VERSION 5.7 ;
BUSBITCHARS "[]" ;
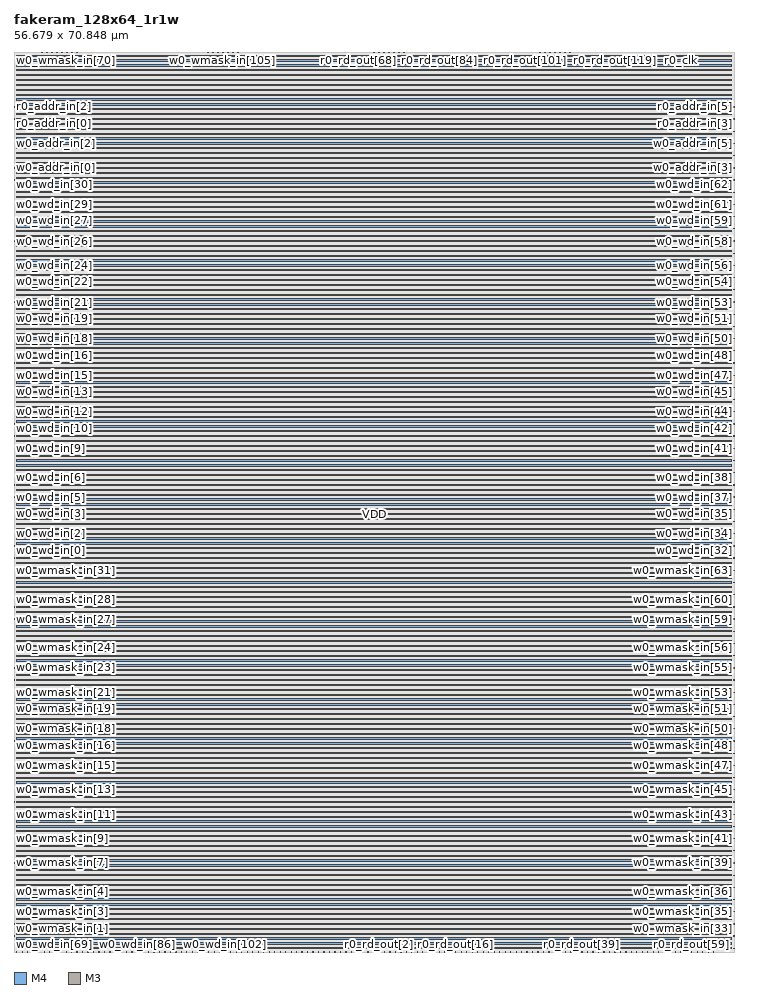
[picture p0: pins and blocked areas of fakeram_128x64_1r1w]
MACRO fakeram_128x64_1r1w
  FOREIGN fakeram_128x64_1r1w 0 0 ;
  SYMMETRY X Y R90 ;
  SIZE 56.679 BY 70.848 ;
  CLASS BLOCK ;
  PIN w0_wmask_in[0]
    DIRECTION INPUT ;
    USE SIGNAL ;
    SHAPE ABUTMENT ;
    PORT
      LAYER M4 ;
      RECT 0.000 0.276 0.072 0.300 ;
    END
  END w0_wmask_in[0]
  PIN w0_wmask_in[1]
    DIRECTION INPUT ;
    USE SIGNAL ;
    SHAPE ABUTMENT ;
    PORT
      LAYER M4 ;
      RECT 0.000 1.236 0.072 1.260 ;
    END
  END w0_wmask_in[1]
  PIN w0_wmask_in[2]
    DIRECTION INPUT ;
    USE SIGNAL ;
    SHAPE ABUTMENT ;
    PORT
      LAYER M4 ;
      RECT 0.000 2.196 0.072 2.220 ;
    END
  END w0_wmask_in[2]
  PIN w0_wmask_in[3]
    DIRECTION INPUT ;
    USE SIGNAL ;
    SHAPE ABUTMENT ;
    PORT
      LAYER M4 ;
      RECT 0.000 3.156 0.072 3.180 ;
    END
  END w0_wmask_in[3]
  PIN w0_wmask_in[4]
    DIRECTION INPUT ;
    USE SIGNAL ;
    SHAPE ABUTMENT ;
    PORT
      LAYER M4 ;
      RECT 0.000 4.116 0.072 4.140 ;
    END
  END w0_wmask_in[4]
  PIN w0_wmask_in[5]
    DIRECTION INPUT ;
    USE SIGNAL ;
    SHAPE ABUTMENT ;
    PORT
      LAYER M4 ;
      RECT 0.000 5.076 0.072 5.100 ;
    END
  END w0_wmask_in[5]
  PIN w0_wmask_in[6]
    DIRECTION INPUT ;
    USE SIGNAL ;
    SHAPE ABUTMENT ;
    PORT
      LAYER M4 ;
      RECT 0.000 6.036 0.072 6.060 ;
    END
  END w0_wmask_in[6]
  PIN w0_wmask_in[7]
    DIRECTION INPUT ;
    USE SIGNAL ;
    SHAPE ABUTMENT ;
    PORT
      LAYER M4 ;
      RECT 0.000 6.996 0.072 7.020 ;
    END
  END w0_wmask_in[7]
  PIN w0_wmask_in[8]
    DIRECTION INPUT ;
    USE SIGNAL ;
    SHAPE ABUTMENT ;
    PORT
      LAYER M4 ;
      RECT 0.000 7.956 0.072 7.980 ;
    END
  END w0_wmask_in[8]
  PIN w0_wmask_in[9]
    DIRECTION INPUT ;
    USE SIGNAL ;
    SHAPE ABUTMENT ;
    PORT
      LAYER M4 ;
      RECT 0.000 8.916 0.072 8.940 ;
    END
  END w0_wmask_in[9]
  PIN w0_wmask_in[10]
    DIRECTION INPUT ;
    USE SIGNAL ;
    SHAPE ABUTMENT ;
    PORT
      LAYER M4 ;
      RECT 0.000 9.876 0.072 9.900 ;
    END
  END w0_wmask_in[10]
  PIN w0_wmask_in[11]
    DIRECTION INPUT ;
    USE SIGNAL ;
    SHAPE ABUTMENT ;
    PORT
      LAYER M4 ;
      RECT 0.000 10.836 0.072 10.860 ;
    END
  END w0_wmask_in[11]
  PIN w0_wmask_in[12]
    DIRECTION INPUT ;
    USE SIGNAL ;
    SHAPE ABUTMENT ;
    PORT
      LAYER M4 ;
      RECT 0.000 11.796 0.072 11.820 ;
    END
  END w0_wmask_in[12]
  PIN w0_wmask_in[13]
    DIRECTION INPUT ;
    USE SIGNAL ;
    SHAPE ABUTMENT ;
    PORT
      LAYER M4 ;
      RECT 0.000 12.756 0.072 12.780 ;
    END
  END w0_wmask_in[13]
  PIN w0_wmask_in[14]
    DIRECTION INPUT ;
    USE SIGNAL ;
    SHAPE ABUTMENT ;
    PORT
      LAYER M4 ;
      RECT 0.000 13.716 0.072 13.740 ;
    END
  END w0_wmask_in[14]
  PIN w0_wmask_in[15]
    DIRECTION INPUT ;
    USE SIGNAL ;
    SHAPE ABUTMENT ;
    PORT
      LAYER M4 ;
      RECT 0.000 14.676 0.072 14.700 ;
    END
  END w0_wmask_in[15]
  PIN w0_wmask_in[16]
    DIRECTION INPUT ;
    USE SIGNAL ;
    SHAPE ABUTMENT ;
    PORT
      LAYER M4 ;
      RECT 0.000 15.636 0.072 15.660 ;
    END
  END w0_wmask_in[16]
  PIN w0_wmask_in[17]
    DIRECTION INPUT ;
    USE SIGNAL ;
    SHAPE ABUTMENT ;
    PORT
      LAYER M4 ;
      RECT 0.000 16.596 0.072 16.620 ;
    END
  END w0_wmask_in[17]
  PIN w0_wmask_in[18]
    DIRECTION INPUT ;
    USE SIGNAL ;
    SHAPE ABUTMENT ;
    PORT
      LAYER M4 ;
      RECT 0.000 17.556 0.072 17.580 ;
    END
  END w0_wmask_in[18]
  PIN w0_wmask_in[19]
    DIRECTION INPUT ;
    USE SIGNAL ;
    SHAPE ABUTMENT ;
    PORT
      LAYER M4 ;
      RECT 0.000 18.516 0.072 18.540 ;
    END
  END w0_wmask_in[19]
  PIN w0_wmask_in[20]
    DIRECTION INPUT ;
    USE SIGNAL ;
    SHAPE ABUTMENT ;
    PORT
      LAYER M4 ;
      RECT 0.000 19.476 0.072 19.500 ;
    END
  END w0_wmask_in[20]
  PIN w0_wmask_in[21]
    DIRECTION INPUT ;
    USE SIGNAL ;
    SHAPE ABUTMENT ;
    PORT
      LAYER M4 ;
      RECT 0.000 20.436 0.072 20.460 ;
    END
  END w0_wmask_in[21]
  PIN w0_wmask_in[22]
    DIRECTION INPUT ;
    USE SIGNAL ;
    SHAPE ABUTMENT ;
    PORT
      LAYER M4 ;
      RECT 0.000 21.396 0.072 21.420 ;
    END
  END w0_wmask_in[22]
  PIN w0_wmask_in[23]
    DIRECTION INPUT ;
    USE SIGNAL ;
    SHAPE ABUTMENT ;
    PORT
      LAYER M4 ;
      RECT 0.000 22.356 0.072 22.380 ;
    END
  END w0_wmask_in[23]
  PIN w0_wmask_in[24]
    DIRECTION INPUT ;
    USE SIGNAL ;
    SHAPE ABUTMENT ;
    PORT
      LAYER M4 ;
      RECT 0.000 23.316 0.072 23.340 ;
    END
  END w0_wmask_in[24]
  PIN w0_wmask_in[25]
    DIRECTION INPUT ;
    USE SIGNAL ;
    SHAPE ABUTMENT ;
    PORT
      LAYER M4 ;
      RECT 0.000 24.276 0.072 24.300 ;
    END
  END w0_wmask_in[25]
  PIN w0_wmask_in[26]
    DIRECTION INPUT ;
    USE SIGNAL ;
    SHAPE ABUTMENT ;
    PORT
      LAYER M4 ;
      RECT 0.000 25.236 0.072 25.260 ;
    END
  END w0_wmask_in[26]
  PIN w0_wmask_in[27]
    DIRECTION INPUT ;
    USE SIGNAL ;
    SHAPE ABUTMENT ;
    PORT
      LAYER M4 ;
      RECT 0.000 26.196 0.072 26.220 ;
    END
  END w0_wmask_in[27]
  PIN w0_wmask_in[28]
    DIRECTION INPUT ;
    USE SIGNAL ;
    SHAPE ABUTMENT ;
    PORT
      LAYER M4 ;
      RECT 0.000 27.156 0.072 27.180 ;
    END
  END w0_wmask_in[28]
  PIN w0_wmask_in[29]
    DIRECTION INPUT ;
    USE SIGNAL ;
    SHAPE ABUTMENT ;
    PORT
      LAYER M4 ;
      RECT 0.000 28.116 0.072 28.140 ;
    END
  END w0_wmask_in[29]
  PIN w0_wmask_in[30]
    DIRECTION INPUT ;
    USE SIGNAL ;
    SHAPE ABUTMENT ;
    PORT
      LAYER M4 ;
      RECT 0.000 29.076 0.072 29.100 ;
    END
  END w0_wmask_in[30]
  PIN w0_wmask_in[31]
    DIRECTION INPUT ;
    USE SIGNAL ;
    SHAPE ABUTMENT ;
    PORT
      LAYER M4 ;
      RECT 0.000 30.036 0.072 30.060 ;
    END
  END w0_wmask_in[31]
  PIN w0_wmask_in[32]
    DIRECTION INPUT ;
    USE SIGNAL ;
    SHAPE ABUTMENT ;
    PORT
      LAYER M4 ;
      RECT 56.607 0.276 56.679 0.300 ;
    END
  END w0_wmask_in[32]
  PIN w0_wmask_in[33]
    DIRECTION INPUT ;
    USE SIGNAL ;
    SHAPE ABUTMENT ;
    PORT
      LAYER M4 ;
      RECT 56.607 1.236 56.679 1.260 ;
    END
  END w0_wmask_in[33]
  PIN w0_wmask_in[34]
    DIRECTION INPUT ;
    USE SIGNAL ;
    SHAPE ABUTMENT ;
    PORT
      LAYER M4 ;
      RECT 56.607 2.196 56.679 2.220 ;
    END
  END w0_wmask_in[34]
  PIN w0_wmask_in[35]
    DIRECTION INPUT ;
    USE SIGNAL ;
    SHAPE ABUTMENT ;
    PORT
      LAYER M4 ;
      RECT 56.607 3.156 56.679 3.180 ;
    END
  END w0_wmask_in[35]
  PIN w0_wmask_in[36]
    DIRECTION INPUT ;
    USE SIGNAL ;
    SHAPE ABUTMENT ;
    PORT
      LAYER M4 ;
      RECT 56.607 4.116 56.679 4.140 ;
    END
  END w0_wmask_in[36]
  PIN w0_wmask_in[37]
    DIRECTION INPUT ;
    USE SIGNAL ;
    SHAPE ABUTMENT ;
    PORT
      LAYER M4 ;
      RECT 56.607 5.076 56.679 5.100 ;
    END
  END w0_wmask_in[37]
  PIN w0_wmask_in[38]
    DIRECTION INPUT ;
    USE SIGNAL ;
    SHAPE ABUTMENT ;
    PORT
      LAYER M4 ;
      RECT 56.607 6.036 56.679 6.060 ;
    END
  END w0_wmask_in[38]
  PIN w0_wmask_in[39]
    DIRECTION INPUT ;
    USE SIGNAL ;
    SHAPE ABUTMENT ;
    PORT
      LAYER M4 ;
      RECT 56.607 6.996 56.679 7.020 ;
    END
  END w0_wmask_in[39]
  PIN w0_wmask_in[40]
    DIRECTION INPUT ;
    USE SIGNAL ;
    SHAPE ABUTMENT ;
    PORT
      LAYER M4 ;
      RECT 56.607 7.956 56.679 7.980 ;
    END
  END w0_wmask_in[40]
  PIN w0_wmask_in[41]
    DIRECTION INPUT ;
    USE SIGNAL ;
    SHAPE ABUTMENT ;
    PORT
      LAYER M4 ;
      RECT 56.607 8.916 56.679 8.940 ;
    END
  END w0_wmask_in[41]
  PIN w0_wmask_in[42]
    DIRECTION INPUT ;
    USE SIGNAL ;
    SHAPE ABUTMENT ;
    PORT
      LAYER M4 ;
      RECT 56.607 9.876 56.679 9.900 ;
    END
  END w0_wmask_in[42]
  PIN w0_wmask_in[43]
    DIRECTION INPUT ;
    USE SIGNAL ;
    SHAPE ABUTMENT ;
    PORT
      LAYER M4 ;
      RECT 56.607 10.836 56.679 10.860 ;
    END
  END w0_wmask_in[43]
  PIN w0_wmask_in[44]
    DIRECTION INPUT ;
    USE SIGNAL ;
    SHAPE ABUTMENT ;
    PORT
      LAYER M4 ;
      RECT 56.607 11.796 56.679 11.820 ;
    END
  END w0_wmask_in[44]
  PIN w0_wmask_in[45]
    DIRECTION INPUT ;
    USE SIGNAL ;
    SHAPE ABUTMENT ;
    PORT
      LAYER M4 ;
      RECT 56.607 12.756 56.679 12.780 ;
    END
  END w0_wmask_in[45]
  PIN w0_wmask_in[46]
    DIRECTION INPUT ;
    USE SIGNAL ;
    SHAPE ABUTMENT ;
    PORT
      LAYER M4 ;
      RECT 56.607 13.716 56.679 13.740 ;
    END
  END w0_wmask_in[46]
  PIN w0_wmask_in[47]
    DIRECTION INPUT ;
    USE SIGNAL ;
    SHAPE ABUTMENT ;
    PORT
      LAYER M4 ;
      RECT 56.607 14.676 56.679 14.700 ;
    END
  END w0_wmask_in[47]
  PIN w0_wmask_in[48]
    DIRECTION INPUT ;
    USE SIGNAL ;
    SHAPE ABUTMENT ;
    PORT
      LAYER M4 ;
      RECT 56.607 15.636 56.679 15.660 ;
    END
  END w0_wmask_in[48]
  PIN w0_wmask_in[49]
    DIRECTION INPUT ;
    USE SIGNAL ;
    SHAPE ABUTMENT ;
    PORT
      LAYER M4 ;
      RECT 56.607 16.596 56.679 16.620 ;
    END
  END w0_wmask_in[49]
  PIN w0_wmask_in[50]
    DIRECTION INPUT ;
    USE SIGNAL ;
    SHAPE ABUTMENT ;
    PORT
      LAYER M4 ;
      RECT 56.607 17.556 56.679 17.580 ;
    END
  END w0_wmask_in[50]
  PIN w0_wmask_in[51]
    DIRECTION INPUT ;
    USE SIGNAL ;
    SHAPE ABUTMENT ;
    PORT
      LAYER M4 ;
      RECT 56.607 18.516 56.679 18.540 ;
    END
  END w0_wmask_in[51]
  PIN w0_wmask_in[52]
    DIRECTION INPUT ;
    USE SIGNAL ;
    SHAPE ABUTMENT ;
    PORT
      LAYER M4 ;
      RECT 56.607 19.476 56.679 19.500 ;
    END
  END w0_wmask_in[52]
  PIN w0_wmask_in[53]
    DIRECTION INPUT ;
    USE SIGNAL ;
    SHAPE ABUTMENT ;
    PORT
      LAYER M4 ;
      RECT 56.607 20.436 56.679 20.460 ;
    END
  END w0_wmask_in[53]
  PIN w0_wmask_in[54]
    DIRECTION INPUT ;
    USE SIGNAL ;
    SHAPE ABUTMENT ;
    PORT
      LAYER M4 ;
      RECT 56.607 21.396 56.679 21.420 ;
    END
  END w0_wmask_in[54]
  PIN w0_wmask_in[55]
    DIRECTION INPUT ;
    USE SIGNAL ;
    SHAPE ABUTMENT ;
    PORT
      LAYER M4 ;
      RECT 56.607 22.356 56.679 22.380 ;
    END
  END w0_wmask_in[55]
  PIN w0_wmask_in[56]
    DIRECTION INPUT ;
    USE SIGNAL ;
    SHAPE ABUTMENT ;
    PORT
      LAYER M4 ;
      RECT 56.607 23.316 56.679 23.340 ;
    END
  END w0_wmask_in[56]
  PIN w0_wmask_in[57]
    DIRECTION INPUT ;
    USE SIGNAL ;
    SHAPE ABUTMENT ;
    PORT
      LAYER M4 ;
      RECT 56.607 24.276 56.679 24.300 ;
    END
  END w0_wmask_in[57]
  PIN w0_wmask_in[58]
    DIRECTION INPUT ;
    USE SIGNAL ;
    SHAPE ABUTMENT ;
    PORT
      LAYER M4 ;
      RECT 56.607 25.236 56.679 25.260 ;
    END
  END w0_wmask_in[58]
  PIN w0_wmask_in[59]
    DIRECTION INPUT ;
    USE SIGNAL ;
    SHAPE ABUTMENT ;
    PORT
      LAYER M4 ;
      RECT 56.607 26.196 56.679 26.220 ;
    END
  END w0_wmask_in[59]
  PIN w0_wmask_in[60]
    DIRECTION INPUT ;
    USE SIGNAL ;
    SHAPE ABUTMENT ;
    PORT
      LAYER M4 ;
      RECT 56.607 27.156 56.679 27.180 ;
    END
  END w0_wmask_in[60]
  PIN w0_wmask_in[61]
    DIRECTION INPUT ;
    USE SIGNAL ;
    SHAPE ABUTMENT ;
    PORT
      LAYER M4 ;
      RECT 56.607 28.116 56.679 28.140 ;
    END
  END w0_wmask_in[61]
  PIN w0_wmask_in[62]
    DIRECTION INPUT ;
    USE SIGNAL ;
    SHAPE ABUTMENT ;
    PORT
      LAYER M4 ;
      RECT 56.607 29.076 56.679 29.100 ;
    END
  END w0_wmask_in[62]
  PIN w0_wmask_in[63]
    DIRECTION INPUT ;
    USE SIGNAL ;
    SHAPE ABUTMENT ;
    PORT
      LAYER M4 ;
      RECT 56.607 30.036 56.679 30.060 ;
    END
  END w0_wmask_in[63]
  PIN w0_wmask_in[64]
    DIRECTION INPUT ;
    USE SIGNAL ;
    SHAPE ABUTMENT ;
    PORT
      LAYER M3 ;
      RECT 0.207 70.794 0.225 70.848 ;
    END
  END w0_wmask_in[64]
  PIN w0_wmask_in[65]
    DIRECTION INPUT ;
    USE SIGNAL ;
    SHAPE ABUTMENT ;
    PORT
      LAYER M3 ;
      RECT 0.603 70.794 0.621 70.848 ;
    END
  END w0_wmask_in[65]
  PIN w0_wmask_in[66]
    DIRECTION INPUT ;
    USE SIGNAL ;
    SHAPE ABUTMENT ;
    PORT
      LAYER M3 ;
      RECT 0.999 70.794 1.017 70.848 ;
    END
  END w0_wmask_in[66]
  PIN w0_wmask_in[67]
    DIRECTION INPUT ;
    USE SIGNAL ;
    SHAPE ABUTMENT ;
    PORT
      LAYER M3 ;
      RECT 1.395 70.794 1.413 70.848 ;
    END
  END w0_wmask_in[67]
  PIN w0_wmask_in[68]
    DIRECTION INPUT ;
    USE SIGNAL ;
    SHAPE ABUTMENT ;
    PORT
      LAYER M3 ;
      RECT 1.791 70.794 1.809 70.848 ;
    END
  END w0_wmask_in[68]
  PIN w0_wmask_in[69]
    DIRECTION INPUT ;
    USE SIGNAL ;
    SHAPE ABUTMENT ;
    PORT
      LAYER M3 ;
      RECT 2.187 70.794 2.205 70.848 ;
    END
  END w0_wmask_in[69]
  PIN w0_wmask_in[70]
    DIRECTION INPUT ;
    USE SIGNAL ;
    SHAPE ABUTMENT ;
    PORT
      LAYER M3 ;
      RECT 2.583 70.794 2.601 70.848 ;
    END
  END w0_wmask_in[70]
  PIN w0_wmask_in[71]
    DIRECTION INPUT ;
    USE SIGNAL ;
    SHAPE ABUTMENT ;
    PORT
      LAYER M3 ;
      RECT 2.979 70.794 2.997 70.848 ;
    END
  END w0_wmask_in[71]
  PIN w0_wmask_in[72]
    DIRECTION INPUT ;
    USE SIGNAL ;
    SHAPE ABUTMENT ;
    PORT
      LAYER M3 ;
      RECT 3.375 70.794 3.393 70.848 ;
    END
  END w0_wmask_in[72]
  PIN w0_wmask_in[73]
    DIRECTION INPUT ;
    USE SIGNAL ;
    SHAPE ABUTMENT ;
    PORT
      LAYER M3 ;
      RECT 3.771 70.794 3.789 70.848 ;
    END
  END w0_wmask_in[73]
  PIN w0_wmask_in[74]
    DIRECTION INPUT ;
    USE SIGNAL ;
    SHAPE ABUTMENT ;
    PORT
      LAYER M3 ;
      RECT 4.167 70.794 4.185 70.848 ;
    END
  END w0_wmask_in[74]
  PIN w0_wmask_in[75]
    DIRECTION INPUT ;
    USE SIGNAL ;
    SHAPE ABUTMENT ;
    PORT
      LAYER M3 ;
      RECT 4.563 70.794 4.581 70.848 ;
    END
  END w0_wmask_in[75]
  PIN w0_wmask_in[76]
    DIRECTION INPUT ;
    USE SIGNAL ;
    SHAPE ABUTMENT ;
    PORT
      LAYER M3 ;
      RECT 4.959 70.794 4.977 70.848 ;
    END
  END w0_wmask_in[76]
  PIN w0_wmask_in[77]
    DIRECTION INPUT ;
    USE SIGNAL ;
    SHAPE ABUTMENT ;
    PORT
      LAYER M3 ;
      RECT 5.355 70.794 5.373 70.848 ;
    END
  END w0_wmask_in[77]
  PIN w0_wmask_in[78]
    DIRECTION INPUT ;
    USE SIGNAL ;
    SHAPE ABUTMENT ;
    PORT
      LAYER M3 ;
      RECT 5.751 70.794 5.769 70.848 ;
    END
  END w0_wmask_in[78]
  PIN w0_wmask_in[79]
    DIRECTION INPUT ;
    USE SIGNAL ;
    SHAPE ABUTMENT ;
    PORT
      LAYER M3 ;
      RECT 6.147 70.794 6.165 70.848 ;
    END
  END w0_wmask_in[79]
  PIN w0_wmask_in[80]
    DIRECTION INPUT ;
    USE SIGNAL ;
    SHAPE ABUTMENT ;
    PORT
      LAYER M3 ;
      RECT 6.543 70.794 6.561 70.848 ;
    END
  END w0_wmask_in[80]
  PIN w0_wmask_in[81]
    DIRECTION INPUT ;
    USE SIGNAL ;
    SHAPE ABUTMENT ;
    PORT
      LAYER M3 ;
      RECT 6.939 70.794 6.957 70.848 ;
    END
  END w0_wmask_in[81]
  PIN w0_wmask_in[82]
    DIRECTION INPUT ;
    USE SIGNAL ;
    SHAPE ABUTMENT ;
    PORT
      LAYER M3 ;
      RECT 7.335 70.794 7.353 70.848 ;
    END
  END w0_wmask_in[82]
  PIN w0_wmask_in[83]
    DIRECTION INPUT ;
    USE SIGNAL ;
    SHAPE ABUTMENT ;
    PORT
      LAYER M3 ;
      RECT 7.731 70.794 7.749 70.848 ;
    END
  END w0_wmask_in[83]
  PIN w0_wmask_in[84]
    DIRECTION INPUT ;
    USE SIGNAL ;
    SHAPE ABUTMENT ;
    PORT
      LAYER M3 ;
      RECT 8.127 70.794 8.145 70.848 ;
    END
  END w0_wmask_in[84]
  PIN w0_wmask_in[85]
    DIRECTION INPUT ;
    USE SIGNAL ;
    SHAPE ABUTMENT ;
    PORT
      LAYER M3 ;
      RECT 8.523 70.794 8.541 70.848 ;
    END
  END w0_wmask_in[85]
  PIN w0_wmask_in[86]
    DIRECTION INPUT ;
    USE SIGNAL ;
    SHAPE ABUTMENT ;
    PORT
      LAYER M3 ;
      RECT 8.919 70.794 8.937 70.848 ;
    END
  END w0_wmask_in[86]
  PIN w0_wmask_in[87]
    DIRECTION INPUT ;
    USE SIGNAL ;
    SHAPE ABUTMENT ;
    PORT
      LAYER M3 ;
      RECT 9.315 70.794 9.333 70.848 ;
    END
  END w0_wmask_in[87]
  PIN w0_wmask_in[88]
    DIRECTION INPUT ;
    USE SIGNAL ;
    SHAPE ABUTMENT ;
    PORT
      LAYER M3 ;
      RECT 9.711 70.794 9.729 70.848 ;
    END
  END w0_wmask_in[88]
  PIN w0_wmask_in[89]
    DIRECTION INPUT ;
    USE SIGNAL ;
    SHAPE ABUTMENT ;
    PORT
      LAYER M3 ;
      RECT 10.107 70.794 10.125 70.848 ;
    END
  END w0_wmask_in[89]
  PIN w0_wmask_in[90]
    DIRECTION INPUT ;
    USE SIGNAL ;
    SHAPE ABUTMENT ;
    PORT
      LAYER M3 ;
      RECT 10.503 70.794 10.521 70.848 ;
    END
  END w0_wmask_in[90]
  PIN w0_wmask_in[91]
    DIRECTION INPUT ;
    USE SIGNAL ;
    SHAPE ABUTMENT ;
    PORT
      LAYER M3 ;
      RECT 10.899 70.794 10.917 70.848 ;
    END
  END w0_wmask_in[91]
  PIN w0_wmask_in[92]
    DIRECTION INPUT ;
    USE SIGNAL ;
    SHAPE ABUTMENT ;
    PORT
      LAYER M3 ;
      RECT 11.295 70.794 11.313 70.848 ;
    END
  END w0_wmask_in[92]
  PIN w0_wmask_in[93]
    DIRECTION INPUT ;
    USE SIGNAL ;
    SHAPE ABUTMENT ;
    PORT
      LAYER M3 ;
      RECT 11.691 70.794 11.709 70.848 ;
    END
  END w0_wmask_in[93]
  PIN w0_wmask_in[94]
    DIRECTION INPUT ;
    USE SIGNAL ;
    SHAPE ABUTMENT ;
    PORT
      LAYER M3 ;
      RECT 12.087 70.794 12.105 70.848 ;
    END
  END w0_wmask_in[94]
  PIN w0_wmask_in[95]
    DIRECTION INPUT ;
    USE SIGNAL ;
    SHAPE ABUTMENT ;
    PORT
      LAYER M3 ;
      RECT 12.483 70.794 12.501 70.848 ;
    END
  END w0_wmask_in[95]
  PIN w0_wmask_in[96]
    DIRECTION INPUT ;
    USE SIGNAL ;
    SHAPE ABUTMENT ;
    PORT
      LAYER M3 ;
      RECT 12.879 70.794 12.897 70.848 ;
    END
  END w0_wmask_in[96]
  PIN w0_wmask_in[97]
    DIRECTION INPUT ;
    USE SIGNAL ;
    SHAPE ABUTMENT ;
    PORT
      LAYER M3 ;
      RECT 13.275 70.794 13.293 70.848 ;
    END
  END w0_wmask_in[97]
  PIN w0_wmask_in[98]
    DIRECTION INPUT ;
    USE SIGNAL ;
    SHAPE ABUTMENT ;
    PORT
      LAYER M3 ;
      RECT 13.671 70.794 13.689 70.848 ;
    END
  END w0_wmask_in[98]
  PIN w0_wmask_in[99]
    DIRECTION INPUT ;
    USE SIGNAL ;
    SHAPE ABUTMENT ;
    PORT
      LAYER M3 ;
      RECT 14.067 70.794 14.085 70.848 ;
    END
  END w0_wmask_in[99]
  PIN w0_wmask_in[100]
    DIRECTION INPUT ;
    USE SIGNAL ;
    SHAPE ABUTMENT ;
    PORT
      LAYER M3 ;
      RECT 14.463 70.794 14.481 70.848 ;
    END
  END w0_wmask_in[100]
  PIN w0_wmask_in[101]
    DIRECTION INPUT ;
    USE SIGNAL ;
    SHAPE ABUTMENT ;
    PORT
      LAYER M3 ;
      RECT 14.859 70.794 14.877 70.848 ;
    END
  END w0_wmask_in[101]
  PIN w0_wmask_in[102]
    DIRECTION INPUT ;
    USE SIGNAL ;
    SHAPE ABUTMENT ;
    PORT
      LAYER M3 ;
      RECT 15.255 70.794 15.273 70.848 ;
    END
  END w0_wmask_in[102]
  PIN w0_wmask_in[103]
    DIRECTION INPUT ;
    USE SIGNAL ;
    SHAPE ABUTMENT ;
    PORT
      LAYER M3 ;
      RECT 15.651 70.794 15.669 70.848 ;
    END
  END w0_wmask_in[103]
  PIN w0_wmask_in[104]
    DIRECTION INPUT ;
    USE SIGNAL ;
    SHAPE ABUTMENT ;
    PORT
      LAYER M3 ;
      RECT 16.047 70.794 16.065 70.848 ;
    END
  END w0_wmask_in[104]
  PIN w0_wmask_in[105]
    DIRECTION INPUT ;
    USE SIGNAL ;
    SHAPE ABUTMENT ;
    PORT
      LAYER M3 ;
      RECT 16.443 70.794 16.461 70.848 ;
    END
  END w0_wmask_in[105]
  PIN w0_wmask_in[106]
    DIRECTION INPUT ;
    USE SIGNAL ;
    SHAPE ABUTMENT ;
    PORT
      LAYER M3 ;
      RECT 16.839 70.794 16.857 70.848 ;
    END
  END w0_wmask_in[106]
  PIN w0_wmask_in[107]
    DIRECTION INPUT ;
    USE SIGNAL ;
    SHAPE ABUTMENT ;
    PORT
      LAYER M3 ;
      RECT 17.235 70.794 17.253 70.848 ;
    END
  END w0_wmask_in[107]
  PIN w0_wmask_in[108]
    DIRECTION INPUT ;
    USE SIGNAL ;
    SHAPE ABUTMENT ;
    PORT
      LAYER M3 ;
      RECT 17.631 70.794 17.649 70.848 ;
    END
  END w0_wmask_in[108]
  PIN w0_wmask_in[109]
    DIRECTION INPUT ;
    USE SIGNAL ;
    SHAPE ABUTMENT ;
    PORT
      LAYER M3 ;
      RECT 18.027 70.794 18.045 70.848 ;
    END
  END w0_wmask_in[109]
  PIN w0_wmask_in[110]
    DIRECTION INPUT ;
    USE SIGNAL ;
    SHAPE ABUTMENT ;
    PORT
      LAYER M3 ;
      RECT 18.423 70.794 18.441 70.848 ;
    END
  END w0_wmask_in[110]
  PIN w0_wmask_in[111]
    DIRECTION INPUT ;
    USE SIGNAL ;
    SHAPE ABUTMENT ;
    PORT
      LAYER M3 ;
      RECT 18.819 70.794 18.837 70.848 ;
    END
  END w0_wmask_in[111]
  PIN w0_wmask_in[112]
    DIRECTION INPUT ;
    USE SIGNAL ;
    SHAPE ABUTMENT ;
    PORT
      LAYER M3 ;
      RECT 19.215 70.794 19.233 70.848 ;
    END
  END w0_wmask_in[112]
  PIN w0_wmask_in[113]
    DIRECTION INPUT ;
    USE SIGNAL ;
    SHAPE ABUTMENT ;
    PORT
      LAYER M3 ;
      RECT 19.611 70.794 19.629 70.848 ;
    END
  END w0_wmask_in[113]
  PIN w0_wmask_in[114]
    DIRECTION INPUT ;
    USE SIGNAL ;
    SHAPE ABUTMENT ;
    PORT
      LAYER M3 ;
      RECT 20.007 70.794 20.025 70.848 ;
    END
  END w0_wmask_in[114]
  PIN w0_wmask_in[115]
    DIRECTION INPUT ;
    USE SIGNAL ;
    SHAPE ABUTMENT ;
    PORT
      LAYER M3 ;
      RECT 20.403 70.794 20.421 70.848 ;
    END
  END w0_wmask_in[115]
  PIN w0_wmask_in[116]
    DIRECTION INPUT ;
    USE SIGNAL ;
    SHAPE ABUTMENT ;
    PORT
      LAYER M3 ;
      RECT 20.799 70.794 20.817 70.848 ;
    END
  END w0_wmask_in[116]
  PIN w0_wmask_in[117]
    DIRECTION INPUT ;
    USE SIGNAL ;
    SHAPE ABUTMENT ;
    PORT
      LAYER M3 ;
      RECT 21.195 70.794 21.213 70.848 ;
    END
  END w0_wmask_in[117]
  PIN w0_wmask_in[118]
    DIRECTION INPUT ;
    USE SIGNAL ;
    SHAPE ABUTMENT ;
    PORT
      LAYER M3 ;
      RECT 21.591 70.794 21.609 70.848 ;
    END
  END w0_wmask_in[118]
  PIN w0_wmask_in[119]
    DIRECTION INPUT ;
    USE SIGNAL ;
    SHAPE ABUTMENT ;
    PORT
      LAYER M3 ;
      RECT 21.987 70.794 22.005 70.848 ;
    END
  END w0_wmask_in[119]
  PIN w0_wmask_in[120]
    DIRECTION INPUT ;
    USE SIGNAL ;
    SHAPE ABUTMENT ;
    PORT
      LAYER M3 ;
      RECT 22.383 70.794 22.401 70.848 ;
    END
  END w0_wmask_in[120]
  PIN w0_wmask_in[121]
    DIRECTION INPUT ;
    USE SIGNAL ;
    SHAPE ABUTMENT ;
    PORT
      LAYER M3 ;
      RECT 22.779 70.794 22.797 70.848 ;
    END
  END w0_wmask_in[121]
  PIN w0_wmask_in[122]
    DIRECTION INPUT ;
    USE SIGNAL ;
    SHAPE ABUTMENT ;
    PORT
      LAYER M3 ;
      RECT 23.175 70.794 23.193 70.848 ;
    END
  END w0_wmask_in[122]
  PIN w0_wmask_in[123]
    DIRECTION INPUT ;
    USE SIGNAL ;
    SHAPE ABUTMENT ;
    PORT
      LAYER M3 ;
      RECT 23.571 70.794 23.589 70.848 ;
    END
  END w0_wmask_in[123]
  PIN w0_wmask_in[124]
    DIRECTION INPUT ;
    USE SIGNAL ;
    SHAPE ABUTMENT ;
    PORT
      LAYER M3 ;
      RECT 23.967 70.794 23.985 70.848 ;
    END
  END w0_wmask_in[124]
  PIN w0_wmask_in[125]
    DIRECTION INPUT ;
    USE SIGNAL ;
    SHAPE ABUTMENT ;
    PORT
      LAYER M3 ;
      RECT 24.363 70.794 24.381 70.848 ;
    END
  END w0_wmask_in[125]
  PIN w0_wmask_in[126]
    DIRECTION INPUT ;
    USE SIGNAL ;
    SHAPE ABUTMENT ;
    PORT
      LAYER M3 ;
      RECT 24.759 70.794 24.777 70.848 ;
    END
  END w0_wmask_in[126]
  PIN w0_wmask_in[127]
    DIRECTION INPUT ;
    USE SIGNAL ;
    SHAPE ABUTMENT ;
    PORT
      LAYER M3 ;
      RECT 25.155 70.794 25.173 70.848 ;
    END
  END w0_wmask_in[127]
  PIN w0_wd_in[0]
    DIRECTION INPUT ;
    USE SIGNAL ;
    SHAPE ABUTMENT ;
    PORT
      LAYER M4 ;
      RECT 0.000 30.996 0.072 31.020 ;
    END
  END w0_wd_in[0]
  PIN w0_wd_in[1]
    DIRECTION INPUT ;
    USE SIGNAL ;
    SHAPE ABUTMENT ;
    PORT
      LAYER M4 ;
      RECT 0.000 31.956 0.072 31.980 ;
    END
  END w0_wd_in[1]
  PIN w0_wd_in[2]
    DIRECTION INPUT ;
    USE SIGNAL ;
    SHAPE ABUTMENT ;
    PORT
      LAYER M4 ;
      RECT 0.000 32.916 0.072 32.940 ;
    END
  END w0_wd_in[2]
  PIN w0_wd_in[3]
    DIRECTION INPUT ;
    USE SIGNAL ;
    SHAPE ABUTMENT ;
    PORT
      LAYER M4 ;
      RECT 0.000 33.876 0.072 33.900 ;
    END
  END w0_wd_in[3]
  PIN w0_wd_in[4]
    DIRECTION INPUT ;
    USE SIGNAL ;
    SHAPE ABUTMENT ;
    PORT
      LAYER M4 ;
      RECT 0.000 34.836 0.072 34.860 ;
    END
  END w0_wd_in[4]
  PIN w0_wd_in[5]
    DIRECTION INPUT ;
    USE SIGNAL ;
    SHAPE ABUTMENT ;
    PORT
      LAYER M4 ;
      RECT 0.000 35.796 0.072 35.820 ;
    END
  END w0_wd_in[5]
  PIN w0_wd_in[6]
    DIRECTION INPUT ;
    USE SIGNAL ;
    SHAPE ABUTMENT ;
    PORT
      LAYER M4 ;
      RECT 0.000 36.756 0.072 36.780 ;
    END
  END w0_wd_in[6]
  PIN w0_wd_in[7]
    DIRECTION INPUT ;
    USE SIGNAL ;
    SHAPE ABUTMENT ;
    PORT
      LAYER M4 ;
      RECT 0.000 37.716 0.072 37.740 ;
    END
  END w0_wd_in[7]
  PIN w0_wd_in[8]
    DIRECTION INPUT ;
    USE SIGNAL ;
    SHAPE ABUTMENT ;
    PORT
      LAYER M4 ;
      RECT 0.000 38.676 0.072 38.700 ;
    END
  END w0_wd_in[8]
  PIN w0_wd_in[9]
    DIRECTION INPUT ;
    USE SIGNAL ;
    SHAPE ABUTMENT ;
    PORT
      LAYER M4 ;
      RECT 0.000 39.636 0.072 39.660 ;
    END
  END w0_wd_in[9]
  PIN w0_wd_in[10]
    DIRECTION INPUT ;
    USE SIGNAL ;
    SHAPE ABUTMENT ;
    PORT
      LAYER M4 ;
      RECT 0.000 40.596 0.072 40.620 ;
    END
  END w0_wd_in[10]
  PIN w0_wd_in[11]
    DIRECTION INPUT ;
    USE SIGNAL ;
    SHAPE ABUTMENT ;
    PORT
      LAYER M4 ;
      RECT 0.000 41.556 0.072 41.580 ;
    END
  END w0_wd_in[11]
  PIN w0_wd_in[12]
    DIRECTION INPUT ;
    USE SIGNAL ;
    SHAPE ABUTMENT ;
    PORT
      LAYER M4 ;
      RECT 0.000 42.516 0.072 42.540 ;
    END
  END w0_wd_in[12]
  PIN w0_wd_in[13]
    DIRECTION INPUT ;
    USE SIGNAL ;
    SHAPE ABUTMENT ;
    PORT
      LAYER M4 ;
      RECT 0.000 43.476 0.072 43.500 ;
    END
  END w0_wd_in[13]
  PIN w0_wd_in[14]
    DIRECTION INPUT ;
    USE SIGNAL ;
    SHAPE ABUTMENT ;
    PORT
      LAYER M4 ;
      RECT 0.000 44.436 0.072 44.460 ;
    END
  END w0_wd_in[14]
  PIN w0_wd_in[15]
    DIRECTION INPUT ;
    USE SIGNAL ;
    SHAPE ABUTMENT ;
    PORT
      LAYER M4 ;
      RECT 0.000 45.396 0.072 45.420 ;
    END
  END w0_wd_in[15]
  PIN w0_wd_in[16]
    DIRECTION INPUT ;
    USE SIGNAL ;
    SHAPE ABUTMENT ;
    PORT
      LAYER M4 ;
      RECT 0.000 46.356 0.072 46.380 ;
    END
  END w0_wd_in[16]
  PIN w0_wd_in[17]
    DIRECTION INPUT ;
    USE SIGNAL ;
    SHAPE ABUTMENT ;
    PORT
      LAYER M4 ;
      RECT 0.000 47.316 0.072 47.340 ;
    END
  END w0_wd_in[17]
  PIN w0_wd_in[18]
    DIRECTION INPUT ;
    USE SIGNAL ;
    SHAPE ABUTMENT ;
    PORT
      LAYER M4 ;
      RECT 0.000 48.276 0.072 48.300 ;
    END
  END w0_wd_in[18]
  PIN w0_wd_in[19]
    DIRECTION INPUT ;
    USE SIGNAL ;
    SHAPE ABUTMENT ;
    PORT
      LAYER M4 ;
      RECT 0.000 49.236 0.072 49.260 ;
    END
  END w0_wd_in[19]
  PIN w0_wd_in[20]
    DIRECTION INPUT ;
    USE SIGNAL ;
    SHAPE ABUTMENT ;
    PORT
      LAYER M4 ;
      RECT 0.000 50.196 0.072 50.220 ;
    END
  END w0_wd_in[20]
  PIN w0_wd_in[21]
    DIRECTION INPUT ;
    USE SIGNAL ;
    SHAPE ABUTMENT ;
    PORT
      LAYER M4 ;
      RECT 0.000 51.156 0.072 51.180 ;
    END
  END w0_wd_in[21]
  PIN w0_wd_in[22]
    DIRECTION INPUT ;
    USE SIGNAL ;
    SHAPE ABUTMENT ;
    PORT
      LAYER M4 ;
      RECT 0.000 52.116 0.072 52.140 ;
    END
  END w0_wd_in[22]
  PIN w0_wd_in[23]
    DIRECTION INPUT ;
    USE SIGNAL ;
    SHAPE ABUTMENT ;
    PORT
      LAYER M4 ;
      RECT 0.000 53.076 0.072 53.100 ;
    END
  END w0_wd_in[23]
  PIN w0_wd_in[24]
    DIRECTION INPUT ;
    USE SIGNAL ;
    SHAPE ABUTMENT ;
    PORT
      LAYER M4 ;
      RECT 0.000 54.036 0.072 54.060 ;
    END
  END w0_wd_in[24]
  PIN w0_wd_in[25]
    DIRECTION INPUT ;
    USE SIGNAL ;
    SHAPE ABUTMENT ;
    PORT
      LAYER M4 ;
      RECT 0.000 54.996 0.072 55.020 ;
    END
  END w0_wd_in[25]
  PIN w0_wd_in[26]
    DIRECTION INPUT ;
    USE SIGNAL ;
    SHAPE ABUTMENT ;
    PORT
      LAYER M4 ;
      RECT 0.000 55.956 0.072 55.980 ;
    END
  END w0_wd_in[26]
  PIN w0_wd_in[27]
    DIRECTION INPUT ;
    USE SIGNAL ;
    SHAPE ABUTMENT ;
    PORT
      LAYER M4 ;
      RECT 0.000 56.916 0.072 56.940 ;
    END
  END w0_wd_in[27]
  PIN w0_wd_in[28]
    DIRECTION INPUT ;
    USE SIGNAL ;
    SHAPE ABUTMENT ;
    PORT
      LAYER M4 ;
      RECT 0.000 57.876 0.072 57.900 ;
    END
  END w0_wd_in[28]
  PIN w0_wd_in[29]
    DIRECTION INPUT ;
    USE SIGNAL ;
    SHAPE ABUTMENT ;
    PORT
      LAYER M4 ;
      RECT 0.000 58.836 0.072 58.860 ;
    END
  END w0_wd_in[29]
  PIN w0_wd_in[30]
    DIRECTION INPUT ;
    USE SIGNAL ;
    SHAPE ABUTMENT ;
    PORT
      LAYER M4 ;
      RECT 0.000 59.796 0.072 59.820 ;
    END
  END w0_wd_in[30]
  PIN w0_wd_in[31]
    DIRECTION INPUT ;
    USE SIGNAL ;
    SHAPE ABUTMENT ;
    PORT
      LAYER M4 ;
      RECT 0.000 60.756 0.072 60.780 ;
    END
  END w0_wd_in[31]
  PIN w0_wd_in[32]
    DIRECTION INPUT ;
    USE SIGNAL ;
    SHAPE ABUTMENT ;
    PORT
      LAYER M4 ;
      RECT 56.607 30.996 56.679 31.020 ;
    END
  END w0_wd_in[32]
  PIN w0_wd_in[33]
    DIRECTION INPUT ;
    USE SIGNAL ;
    SHAPE ABUTMENT ;
    PORT
      LAYER M4 ;
      RECT 56.607 31.956 56.679 31.980 ;
    END
  END w0_wd_in[33]
  PIN w0_wd_in[34]
    DIRECTION INPUT ;
    USE SIGNAL ;
    SHAPE ABUTMENT ;
    PORT
      LAYER M4 ;
      RECT 56.607 32.916 56.679 32.940 ;
    END
  END w0_wd_in[34]
  PIN w0_wd_in[35]
    DIRECTION INPUT ;
    USE SIGNAL ;
    SHAPE ABUTMENT ;
    PORT
      LAYER M4 ;
      RECT 56.607 33.876 56.679 33.900 ;
    END
  END w0_wd_in[35]
  PIN w0_wd_in[36]
    DIRECTION INPUT ;
    USE SIGNAL ;
    SHAPE ABUTMENT ;
    PORT
      LAYER M4 ;
      RECT 56.607 34.836 56.679 34.860 ;
    END
  END w0_wd_in[36]
  PIN w0_wd_in[37]
    DIRECTION INPUT ;
    USE SIGNAL ;
    SHAPE ABUTMENT ;
    PORT
      LAYER M4 ;
      RECT 56.607 35.796 56.679 35.820 ;
    END
  END w0_wd_in[37]
  PIN w0_wd_in[38]
    DIRECTION INPUT ;
    USE SIGNAL ;
    SHAPE ABUTMENT ;
    PORT
      LAYER M4 ;
      RECT 56.607 36.756 56.679 36.780 ;
    END
  END w0_wd_in[38]
  PIN w0_wd_in[39]
    DIRECTION INPUT ;
    USE SIGNAL ;
    SHAPE ABUTMENT ;
    PORT
      LAYER M4 ;
      RECT 56.607 37.716 56.679 37.740 ;
    END
  END w0_wd_in[39]
  PIN w0_wd_in[40]
    DIRECTION INPUT ;
    USE SIGNAL ;
    SHAPE ABUTMENT ;
    PORT
      LAYER M4 ;
      RECT 56.607 38.676 56.679 38.700 ;
    END
  END w0_wd_in[40]
  PIN w0_wd_in[41]
    DIRECTION INPUT ;
    USE SIGNAL ;
    SHAPE ABUTMENT ;
    PORT
      LAYER M4 ;
      RECT 56.607 39.636 56.679 39.660 ;
    END
  END w0_wd_in[41]
  PIN w0_wd_in[42]
    DIRECTION INPUT ;
    USE SIGNAL ;
    SHAPE ABUTMENT ;
    PORT
      LAYER M4 ;
      RECT 56.607 40.596 56.679 40.620 ;
    END
  END w0_wd_in[42]
  PIN w0_wd_in[43]
    DIRECTION INPUT ;
    USE SIGNAL ;
    SHAPE ABUTMENT ;
    PORT
      LAYER M4 ;
      RECT 56.607 41.556 56.679 41.580 ;
    END
  END w0_wd_in[43]
  PIN w0_wd_in[44]
    DIRECTION INPUT ;
    USE SIGNAL ;
    SHAPE ABUTMENT ;
    PORT
      LAYER M4 ;
      RECT 56.607 42.516 56.679 42.540 ;
    END
  END w0_wd_in[44]
  PIN w0_wd_in[45]
    DIRECTION INPUT ;
    USE SIGNAL ;
    SHAPE ABUTMENT ;
    PORT
      LAYER M4 ;
      RECT 56.607 43.476 56.679 43.500 ;
    END
  END w0_wd_in[45]
  PIN w0_wd_in[46]
    DIRECTION INPUT ;
    USE SIGNAL ;
    SHAPE ABUTMENT ;
    PORT
      LAYER M4 ;
      RECT 56.607 44.436 56.679 44.460 ;
    END
  END w0_wd_in[46]
  PIN w0_wd_in[47]
    DIRECTION INPUT ;
    USE SIGNAL ;
    SHAPE ABUTMENT ;
    PORT
      LAYER M4 ;
      RECT 56.607 45.396 56.679 45.420 ;
    END
  END w0_wd_in[47]
  PIN w0_wd_in[48]
    DIRECTION INPUT ;
    USE SIGNAL ;
    SHAPE ABUTMENT ;
    PORT
      LAYER M4 ;
      RECT 56.607 46.356 56.679 46.380 ;
    END
  END w0_wd_in[48]
  PIN w0_wd_in[49]
    DIRECTION INPUT ;
    USE SIGNAL ;
    SHAPE ABUTMENT ;
    PORT
      LAYER M4 ;
      RECT 56.607 47.316 56.679 47.340 ;
    END
  END w0_wd_in[49]
  PIN w0_wd_in[50]
    DIRECTION INPUT ;
    USE SIGNAL ;
    SHAPE ABUTMENT ;
    PORT
      LAYER M4 ;
      RECT 56.607 48.276 56.679 48.300 ;
    END
  END w0_wd_in[50]
  PIN w0_wd_in[51]
    DIRECTION INPUT ;
    USE SIGNAL ;
    SHAPE ABUTMENT ;
    PORT
      LAYER M4 ;
      RECT 56.607 49.236 56.679 49.260 ;
    END
  END w0_wd_in[51]
  PIN w0_wd_in[52]
    DIRECTION INPUT ;
    USE SIGNAL ;
    SHAPE ABUTMENT ;
    PORT
      LAYER M4 ;
      RECT 56.607 50.196 56.679 50.220 ;
    END
  END w0_wd_in[52]
  PIN w0_wd_in[53]
    DIRECTION INPUT ;
    USE SIGNAL ;
    SHAPE ABUTMENT ;
    PORT
      LAYER M4 ;
      RECT 56.607 51.156 56.679 51.180 ;
    END
  END w0_wd_in[53]
  PIN w0_wd_in[54]
    DIRECTION INPUT ;
    USE SIGNAL ;
    SHAPE ABUTMENT ;
    PORT
      LAYER M4 ;
      RECT 56.607 52.116 56.679 52.140 ;
    END
  END w0_wd_in[54]
  PIN w0_wd_in[55]
    DIRECTION INPUT ;
    USE SIGNAL ;
    SHAPE ABUTMENT ;
    PORT
      LAYER M4 ;
      RECT 56.607 53.076 56.679 53.100 ;
    END
  END w0_wd_in[55]
  PIN w0_wd_in[56]
    DIRECTION INPUT ;
    USE SIGNAL ;
    SHAPE ABUTMENT ;
    PORT
      LAYER M4 ;
      RECT 56.607 54.036 56.679 54.060 ;
    END
  END w0_wd_in[56]
  PIN w0_wd_in[57]
    DIRECTION INPUT ;
    USE SIGNAL ;
    SHAPE ABUTMENT ;
    PORT
      LAYER M4 ;
      RECT 56.607 54.996 56.679 55.020 ;
    END
  END w0_wd_in[57]
  PIN w0_wd_in[58]
    DIRECTION INPUT ;
    USE SIGNAL ;
    SHAPE ABUTMENT ;
    PORT
      LAYER M4 ;
      RECT 56.607 55.956 56.679 55.980 ;
    END
  END w0_wd_in[58]
  PIN w0_wd_in[59]
    DIRECTION INPUT ;
    USE SIGNAL ;
    SHAPE ABUTMENT ;
    PORT
      LAYER M4 ;
      RECT 56.607 56.916 56.679 56.940 ;
    END
  END w0_wd_in[59]
  PIN w0_wd_in[60]
    DIRECTION INPUT ;
    USE SIGNAL ;
    SHAPE ABUTMENT ;
    PORT
      LAYER M4 ;
      RECT 56.607 57.876 56.679 57.900 ;
    END
  END w0_wd_in[60]
  PIN w0_wd_in[61]
    DIRECTION INPUT ;
    USE SIGNAL ;
    SHAPE ABUTMENT ;
    PORT
      LAYER M4 ;
      RECT 56.607 58.836 56.679 58.860 ;
    END
  END w0_wd_in[61]
  PIN w0_wd_in[62]
    DIRECTION INPUT ;
    USE SIGNAL ;
    SHAPE ABUTMENT ;
    PORT
      LAYER M4 ;
      RECT 56.607 59.796 56.679 59.820 ;
    END
  END w0_wd_in[62]
  PIN w0_wd_in[63]
    DIRECTION INPUT ;
    USE SIGNAL ;
    SHAPE ABUTMENT ;
    PORT
      LAYER M4 ;
      RECT 56.607 60.756 56.679 60.780 ;
    END
  END w0_wd_in[63]
  PIN w0_wd_in[64]
    DIRECTION INPUT ;
    USE SIGNAL ;
    SHAPE ABUTMENT ;
    PORT
      LAYER M3 ;
      RECT 0.207 0.000 0.225 0.054 ;
    END
  END w0_wd_in[64]
  PIN w0_wd_in[65]
    DIRECTION INPUT ;
    USE SIGNAL ;
    SHAPE ABUTMENT ;
    PORT
      LAYER M3 ;
      RECT 0.639 0.000 0.657 0.054 ;
    END
  END w0_wd_in[65]
  PIN w0_wd_in[66]
    DIRECTION INPUT ;
    USE SIGNAL ;
    SHAPE ABUTMENT ;
    PORT
      LAYER M3 ;
      RECT 1.071 0.000 1.089 0.054 ;
    END
  END w0_wd_in[66]
  PIN w0_wd_in[67]
    DIRECTION INPUT ;
    USE SIGNAL ;
    SHAPE ABUTMENT ;
    PORT
      LAYER M3 ;
      RECT 1.503 0.000 1.521 0.054 ;
    END
  END w0_wd_in[67]
  PIN w0_wd_in[68]
    DIRECTION INPUT ;
    USE SIGNAL ;
    SHAPE ABUTMENT ;
    PORT
      LAYER M3 ;
      RECT 1.935 0.000 1.953 0.054 ;
    END
  END w0_wd_in[68]
  PIN w0_wd_in[69]
    DIRECTION INPUT ;
    USE SIGNAL ;
    SHAPE ABUTMENT ;
    PORT
      LAYER M3 ;
      RECT 2.367 0.000 2.385 0.054 ;
    END
  END w0_wd_in[69]
  PIN w0_wd_in[70]
    DIRECTION INPUT ;
    USE SIGNAL ;
    SHAPE ABUTMENT ;
    PORT
      LAYER M3 ;
      RECT 2.799 0.000 2.817 0.054 ;
    END
  END w0_wd_in[70]
  PIN w0_wd_in[71]
    DIRECTION INPUT ;
    USE SIGNAL ;
    SHAPE ABUTMENT ;
    PORT
      LAYER M3 ;
      RECT 3.231 0.000 3.249 0.054 ;
    END
  END w0_wd_in[71]
  PIN w0_wd_in[72]
    DIRECTION INPUT ;
    USE SIGNAL ;
    SHAPE ABUTMENT ;
    PORT
      LAYER M3 ;
      RECT 3.663 0.000 3.681 0.054 ;
    END
  END w0_wd_in[72]
  PIN w0_wd_in[73]
    DIRECTION INPUT ;
    USE SIGNAL ;
    SHAPE ABUTMENT ;
    PORT
      LAYER M3 ;
      RECT 4.095 0.000 4.113 0.054 ;
    END
  END w0_wd_in[73]
  PIN w0_wd_in[74]
    DIRECTION INPUT ;
    USE SIGNAL ;
    SHAPE ABUTMENT ;
    PORT
      LAYER M3 ;
      RECT 4.527 0.000 4.545 0.054 ;
    END
  END w0_wd_in[74]
  PIN w0_wd_in[75]
    DIRECTION INPUT ;
    USE SIGNAL ;
    SHAPE ABUTMENT ;
    PORT
      LAYER M3 ;
      RECT 4.959 0.000 4.977 0.054 ;
    END
  END w0_wd_in[75]
  PIN w0_wd_in[76]
    DIRECTION INPUT ;
    USE SIGNAL ;
    SHAPE ABUTMENT ;
    PORT
      LAYER M3 ;
      RECT 5.391 0.000 5.409 0.054 ;
    END
  END w0_wd_in[76]
  PIN w0_wd_in[77]
    DIRECTION INPUT ;
    USE SIGNAL ;
    SHAPE ABUTMENT ;
    PORT
      LAYER M3 ;
      RECT 5.823 0.000 5.841 0.054 ;
    END
  END w0_wd_in[77]
  PIN w0_wd_in[78]
    DIRECTION INPUT ;
    USE SIGNAL ;
    SHAPE ABUTMENT ;
    PORT
      LAYER M3 ;
      RECT 6.255 0.000 6.273 0.054 ;
    END
  END w0_wd_in[78]
  PIN w0_wd_in[79]
    DIRECTION INPUT ;
    USE SIGNAL ;
    SHAPE ABUTMENT ;
    PORT
      LAYER M3 ;
      RECT 6.687 0.000 6.705 0.054 ;
    END
  END w0_wd_in[79]
  PIN w0_wd_in[80]
    DIRECTION INPUT ;
    USE SIGNAL ;
    SHAPE ABUTMENT ;
    PORT
      LAYER M3 ;
      RECT 7.119 0.000 7.137 0.054 ;
    END
  END w0_wd_in[80]
  PIN w0_wd_in[81]
    DIRECTION INPUT ;
    USE SIGNAL ;
    SHAPE ABUTMENT ;
    PORT
      LAYER M3 ;
      RECT 7.551 0.000 7.569 0.054 ;
    END
  END w0_wd_in[81]
  PIN w0_wd_in[82]
    DIRECTION INPUT ;
    USE SIGNAL ;
    SHAPE ABUTMENT ;
    PORT
      LAYER M3 ;
      RECT 7.983 0.000 8.001 0.054 ;
    END
  END w0_wd_in[82]
  PIN w0_wd_in[83]
    DIRECTION INPUT ;
    USE SIGNAL ;
    SHAPE ABUTMENT ;
    PORT
      LAYER M3 ;
      RECT 8.415 0.000 8.433 0.054 ;
    END
  END w0_wd_in[83]
  PIN w0_wd_in[84]
    DIRECTION INPUT ;
    USE SIGNAL ;
    SHAPE ABUTMENT ;
    PORT
      LAYER M3 ;
      RECT 8.847 0.000 8.865 0.054 ;
    END
  END w0_wd_in[84]
  PIN w0_wd_in[85]
    DIRECTION INPUT ;
    USE SIGNAL ;
    SHAPE ABUTMENT ;
    PORT
      LAYER M3 ;
      RECT 9.279 0.000 9.297 0.054 ;
    END
  END w0_wd_in[85]
  PIN w0_wd_in[86]
    DIRECTION INPUT ;
    USE SIGNAL ;
    SHAPE ABUTMENT ;
    PORT
      LAYER M3 ;
      RECT 9.711 0.000 9.729 0.054 ;
    END
  END w0_wd_in[86]
  PIN w0_wd_in[87]
    DIRECTION INPUT ;
    USE SIGNAL ;
    SHAPE ABUTMENT ;
    PORT
      LAYER M3 ;
      RECT 10.143 0.000 10.161 0.054 ;
    END
  END w0_wd_in[87]
  PIN w0_wd_in[88]
    DIRECTION INPUT ;
    USE SIGNAL ;
    SHAPE ABUTMENT ;
    PORT
      LAYER M3 ;
      RECT 10.575 0.000 10.593 0.054 ;
    END
  END w0_wd_in[88]
  PIN w0_wd_in[89]
    DIRECTION INPUT ;
    USE SIGNAL ;
    SHAPE ABUTMENT ;
    PORT
      LAYER M3 ;
      RECT 11.007 0.000 11.025 0.054 ;
    END
  END w0_wd_in[89]
  PIN w0_wd_in[90]
    DIRECTION INPUT ;
    USE SIGNAL ;
    SHAPE ABUTMENT ;
    PORT
      LAYER M3 ;
      RECT 11.439 0.000 11.457 0.054 ;
    END
  END w0_wd_in[90]
  PIN w0_wd_in[91]
    DIRECTION INPUT ;
    USE SIGNAL ;
    SHAPE ABUTMENT ;
    PORT
      LAYER M3 ;
      RECT 11.871 0.000 11.889 0.054 ;
    END
  END w0_wd_in[91]
  PIN w0_wd_in[92]
    DIRECTION INPUT ;
    USE SIGNAL ;
    SHAPE ABUTMENT ;
    PORT
      LAYER M3 ;
      RECT 12.303 0.000 12.321 0.054 ;
    END
  END w0_wd_in[92]
  PIN w0_wd_in[93]
    DIRECTION INPUT ;
    USE SIGNAL ;
    SHAPE ABUTMENT ;
    PORT
      LAYER M3 ;
      RECT 12.735 0.000 12.753 0.054 ;
    END
  END w0_wd_in[93]
  PIN w0_wd_in[94]
    DIRECTION INPUT ;
    USE SIGNAL ;
    SHAPE ABUTMENT ;
    PORT
      LAYER M3 ;
      RECT 13.167 0.000 13.185 0.054 ;
    END
  END w0_wd_in[94]
  PIN w0_wd_in[95]
    DIRECTION INPUT ;
    USE SIGNAL ;
    SHAPE ABUTMENT ;
    PORT
      LAYER M3 ;
      RECT 13.599 0.000 13.617 0.054 ;
    END
  END w0_wd_in[95]
  PIN w0_wd_in[96]
    DIRECTION INPUT ;
    USE SIGNAL ;
    SHAPE ABUTMENT ;
    PORT
      LAYER M3 ;
      RECT 14.031 0.000 14.049 0.054 ;
    END
  END w0_wd_in[96]
  PIN w0_wd_in[97]
    DIRECTION INPUT ;
    USE SIGNAL ;
    SHAPE ABUTMENT ;
    PORT
      LAYER M3 ;
      RECT 14.463 0.000 14.481 0.054 ;
    END
  END w0_wd_in[97]
  PIN w0_wd_in[98]
    DIRECTION INPUT ;
    USE SIGNAL ;
    SHAPE ABUTMENT ;
    PORT
      LAYER M3 ;
      RECT 14.895 0.000 14.913 0.054 ;
    END
  END w0_wd_in[98]
  PIN w0_wd_in[99]
    DIRECTION INPUT ;
    USE SIGNAL ;
    SHAPE ABUTMENT ;
    PORT
      LAYER M3 ;
      RECT 15.327 0.000 15.345 0.054 ;
    END
  END w0_wd_in[99]
  PIN w0_wd_in[100]
    DIRECTION INPUT ;
    USE SIGNAL ;
    SHAPE ABUTMENT ;
    PORT
      LAYER M3 ;
      RECT 15.759 0.000 15.777 0.054 ;
    END
  END w0_wd_in[100]
  PIN w0_wd_in[101]
    DIRECTION INPUT ;
    USE SIGNAL ;
    SHAPE ABUTMENT ;
    PORT
      LAYER M3 ;
      RECT 16.191 0.000 16.209 0.054 ;
    END
  END w0_wd_in[101]
  PIN w0_wd_in[102]
    DIRECTION INPUT ;
    USE SIGNAL ;
    SHAPE ABUTMENT ;
    PORT
      LAYER M3 ;
      RECT 16.623 0.000 16.641 0.054 ;
    END
  END w0_wd_in[102]
  PIN w0_wd_in[103]
    DIRECTION INPUT ;
    USE SIGNAL ;
    SHAPE ABUTMENT ;
    PORT
      LAYER M3 ;
      RECT 17.055 0.000 17.073 0.054 ;
    END
  END w0_wd_in[103]
  PIN w0_wd_in[104]
    DIRECTION INPUT ;
    USE SIGNAL ;
    SHAPE ABUTMENT ;
    PORT
      LAYER M3 ;
      RECT 17.487 0.000 17.505 0.054 ;
    END
  END w0_wd_in[104]
  PIN w0_wd_in[105]
    DIRECTION INPUT ;
    USE SIGNAL ;
    SHAPE ABUTMENT ;
    PORT
      LAYER M3 ;
      RECT 17.919 0.000 17.937 0.054 ;
    END
  END w0_wd_in[105]
  PIN w0_wd_in[106]
    DIRECTION INPUT ;
    USE SIGNAL ;
    SHAPE ABUTMENT ;
    PORT
      LAYER M3 ;
      RECT 18.351 0.000 18.369 0.054 ;
    END
  END w0_wd_in[106]
  PIN w0_wd_in[107]
    DIRECTION INPUT ;
    USE SIGNAL ;
    SHAPE ABUTMENT ;
    PORT
      LAYER M3 ;
      RECT 18.783 0.000 18.801 0.054 ;
    END
  END w0_wd_in[107]
  PIN w0_wd_in[108]
    DIRECTION INPUT ;
    USE SIGNAL ;
    SHAPE ABUTMENT ;
    PORT
      LAYER M3 ;
      RECT 19.215 0.000 19.233 0.054 ;
    END
  END w0_wd_in[108]
  PIN w0_wd_in[109]
    DIRECTION INPUT ;
    USE SIGNAL ;
    SHAPE ABUTMENT ;
    PORT
      LAYER M3 ;
      RECT 19.647 0.000 19.665 0.054 ;
    END
  END w0_wd_in[109]
  PIN w0_wd_in[110]
    DIRECTION INPUT ;
    USE SIGNAL ;
    SHAPE ABUTMENT ;
    PORT
      LAYER M3 ;
      RECT 20.079 0.000 20.097 0.054 ;
    END
  END w0_wd_in[110]
  PIN w0_wd_in[111]
    DIRECTION INPUT ;
    USE SIGNAL ;
    SHAPE ABUTMENT ;
    PORT
      LAYER M3 ;
      RECT 20.511 0.000 20.529 0.054 ;
    END
  END w0_wd_in[111]
  PIN w0_wd_in[112]
    DIRECTION INPUT ;
    USE SIGNAL ;
    SHAPE ABUTMENT ;
    PORT
      LAYER M3 ;
      RECT 20.943 0.000 20.961 0.054 ;
    END
  END w0_wd_in[112]
  PIN w0_wd_in[113]
    DIRECTION INPUT ;
    USE SIGNAL ;
    SHAPE ABUTMENT ;
    PORT
      LAYER M3 ;
      RECT 21.375 0.000 21.393 0.054 ;
    END
  END w0_wd_in[113]
  PIN w0_wd_in[114]
    DIRECTION INPUT ;
    USE SIGNAL ;
    SHAPE ABUTMENT ;
    PORT
      LAYER M3 ;
      RECT 21.807 0.000 21.825 0.054 ;
    END
  END w0_wd_in[114]
  PIN w0_wd_in[115]
    DIRECTION INPUT ;
    USE SIGNAL ;
    SHAPE ABUTMENT ;
    PORT
      LAYER M3 ;
      RECT 22.239 0.000 22.257 0.054 ;
    END
  END w0_wd_in[115]
  PIN w0_wd_in[116]
    DIRECTION INPUT ;
    USE SIGNAL ;
    SHAPE ABUTMENT ;
    PORT
      LAYER M3 ;
      RECT 22.671 0.000 22.689 0.054 ;
    END
  END w0_wd_in[116]
  PIN w0_wd_in[117]
    DIRECTION INPUT ;
    USE SIGNAL ;
    SHAPE ABUTMENT ;
    PORT
      LAYER M3 ;
      RECT 23.103 0.000 23.121 0.054 ;
    END
  END w0_wd_in[117]
  PIN w0_wd_in[118]
    DIRECTION INPUT ;
    USE SIGNAL ;
    SHAPE ABUTMENT ;
    PORT
      LAYER M3 ;
      RECT 23.535 0.000 23.553 0.054 ;
    END
  END w0_wd_in[118]
  PIN w0_wd_in[119]
    DIRECTION INPUT ;
    USE SIGNAL ;
    SHAPE ABUTMENT ;
    PORT
      LAYER M3 ;
      RECT 23.967 0.000 23.985 0.054 ;
    END
  END w0_wd_in[119]
  PIN w0_wd_in[120]
    DIRECTION INPUT ;
    USE SIGNAL ;
    SHAPE ABUTMENT ;
    PORT
      LAYER M3 ;
      RECT 24.399 0.000 24.417 0.054 ;
    END
  END w0_wd_in[120]
  PIN w0_wd_in[121]
    DIRECTION INPUT ;
    USE SIGNAL ;
    SHAPE ABUTMENT ;
    PORT
      LAYER M3 ;
      RECT 24.831 0.000 24.849 0.054 ;
    END
  END w0_wd_in[121]
  PIN w0_wd_in[122]
    DIRECTION INPUT ;
    USE SIGNAL ;
    SHAPE ABUTMENT ;
    PORT
      LAYER M3 ;
      RECT 25.263 0.000 25.281 0.054 ;
    END
  END w0_wd_in[122]
  PIN w0_wd_in[123]
    DIRECTION INPUT ;
    USE SIGNAL ;
    SHAPE ABUTMENT ;
    PORT
      LAYER M3 ;
      RECT 25.695 0.000 25.713 0.054 ;
    END
  END w0_wd_in[123]
  PIN w0_wd_in[124]
    DIRECTION INPUT ;
    USE SIGNAL ;
    SHAPE ABUTMENT ;
    PORT
      LAYER M3 ;
      RECT 26.127 0.000 26.145 0.054 ;
    END
  END w0_wd_in[124]
  PIN w0_wd_in[125]
    DIRECTION INPUT ;
    USE SIGNAL ;
    SHAPE ABUTMENT ;
    PORT
      LAYER M3 ;
      RECT 26.559 0.000 26.577 0.054 ;
    END
  END w0_wd_in[125]
  PIN w0_wd_in[126]
    DIRECTION INPUT ;
    USE SIGNAL ;
    SHAPE ABUTMENT ;
    PORT
      LAYER M3 ;
      RECT 26.991 0.000 27.009 0.054 ;
    END
  END w0_wd_in[126]
  PIN w0_wd_in[127]
    DIRECTION INPUT ;
    USE SIGNAL ;
    SHAPE ABUTMENT ;
    PORT
      LAYER M3 ;
      RECT 27.423 0.000 27.441 0.054 ;
    END
  END w0_wd_in[127]
  PIN r0_rd_out[0]
    DIRECTION OUTPUT ;
    USE SIGNAL ;
    SHAPE ABUTMENT ;
    PORT
      LAYER M3 ;
      RECT 27.855 0.000 27.873 0.054 ;
    END
  END r0_rd_out[0]
  PIN r0_rd_out[1]
    DIRECTION OUTPUT ;
    USE SIGNAL ;
    SHAPE ABUTMENT ;
    PORT
      LAYER M3 ;
      RECT 28.287 0.000 28.305 0.054 ;
    END
  END r0_rd_out[1]
  PIN r0_rd_out[2]
    DIRECTION OUTPUT ;
    USE SIGNAL ;
    SHAPE ABUTMENT ;
    PORT
      LAYER M3 ;
      RECT 28.719 0.000 28.737 0.054 ;
    END
  END r0_rd_out[2]
  PIN r0_rd_out[3]
    DIRECTION OUTPUT ;
    USE SIGNAL ;
    SHAPE ABUTMENT ;
    PORT
      LAYER M3 ;
      RECT 29.151 0.000 29.169 0.054 ;
    END
  END r0_rd_out[3]
  PIN r0_rd_out[4]
    DIRECTION OUTPUT ;
    USE SIGNAL ;
    SHAPE ABUTMENT ;
    PORT
      LAYER M3 ;
      RECT 29.583 0.000 29.601 0.054 ;
    END
  END r0_rd_out[4]
  PIN r0_rd_out[5]
    DIRECTION OUTPUT ;
    USE SIGNAL ;
    SHAPE ABUTMENT ;
    PORT
      LAYER M3 ;
      RECT 30.015 0.000 30.033 0.054 ;
    END
  END r0_rd_out[5]
  PIN r0_rd_out[6]
    DIRECTION OUTPUT ;
    USE SIGNAL ;
    SHAPE ABUTMENT ;
    PORT
      LAYER M3 ;
      RECT 30.447 0.000 30.465 0.054 ;
    END
  END r0_rd_out[6]
  PIN r0_rd_out[7]
    DIRECTION OUTPUT ;
    USE SIGNAL ;
    SHAPE ABUTMENT ;
    PORT
      LAYER M3 ;
      RECT 30.879 0.000 30.897 0.054 ;
    END
  END r0_rd_out[7]
  PIN r0_rd_out[8]
    DIRECTION OUTPUT ;
    USE SIGNAL ;
    SHAPE ABUTMENT ;
    PORT
      LAYER M3 ;
      RECT 31.311 0.000 31.329 0.054 ;
    END
  END r0_rd_out[8]
  PIN r0_rd_out[9]
    DIRECTION OUTPUT ;
    USE SIGNAL ;
    SHAPE ABUTMENT ;
    PORT
      LAYER M3 ;
      RECT 31.743 0.000 31.761 0.054 ;
    END
  END r0_rd_out[9]
  PIN r0_rd_out[10]
    DIRECTION OUTPUT ;
    USE SIGNAL ;
    SHAPE ABUTMENT ;
    PORT
      LAYER M3 ;
      RECT 32.175 0.000 32.193 0.054 ;
    END
  END r0_rd_out[10]
  PIN r0_rd_out[11]
    DIRECTION OUTPUT ;
    USE SIGNAL ;
    SHAPE ABUTMENT ;
    PORT
      LAYER M3 ;
      RECT 32.607 0.000 32.625 0.054 ;
    END
  END r0_rd_out[11]
  PIN r0_rd_out[12]
    DIRECTION OUTPUT ;
    USE SIGNAL ;
    SHAPE ABUTMENT ;
    PORT
      LAYER M3 ;
      RECT 33.039 0.000 33.057 0.054 ;
    END
  END r0_rd_out[12]
  PIN r0_rd_out[13]
    DIRECTION OUTPUT ;
    USE SIGNAL ;
    SHAPE ABUTMENT ;
    PORT
      LAYER M3 ;
      RECT 33.471 0.000 33.489 0.054 ;
    END
  END r0_rd_out[13]
  PIN r0_rd_out[14]
    DIRECTION OUTPUT ;
    USE SIGNAL ;
    SHAPE ABUTMENT ;
    PORT
      LAYER M3 ;
      RECT 33.903 0.000 33.921 0.054 ;
    END
  END r0_rd_out[14]
  PIN r0_rd_out[15]
    DIRECTION OUTPUT ;
    USE SIGNAL ;
    SHAPE ABUTMENT ;
    PORT
      LAYER M3 ;
      RECT 34.335 0.000 34.353 0.054 ;
    END
  END r0_rd_out[15]
  PIN r0_rd_out[16]
    DIRECTION OUTPUT ;
    USE SIGNAL ;
    SHAPE ABUTMENT ;
    PORT
      LAYER M3 ;
      RECT 34.767 0.000 34.785 0.054 ;
    END
  END r0_rd_out[16]
  PIN r0_rd_out[17]
    DIRECTION OUTPUT ;
    USE SIGNAL ;
    SHAPE ABUTMENT ;
    PORT
      LAYER M3 ;
      RECT 35.199 0.000 35.217 0.054 ;
    END
  END r0_rd_out[17]
  PIN r0_rd_out[18]
    DIRECTION OUTPUT ;
    USE SIGNAL ;
    SHAPE ABUTMENT ;
    PORT
      LAYER M3 ;
      RECT 35.631 0.000 35.649 0.054 ;
    END
  END r0_rd_out[18]
  PIN r0_rd_out[19]
    DIRECTION OUTPUT ;
    USE SIGNAL ;
    SHAPE ABUTMENT ;
    PORT
      LAYER M3 ;
      RECT 36.063 0.000 36.081 0.054 ;
    END
  END r0_rd_out[19]
  PIN r0_rd_out[20]
    DIRECTION OUTPUT ;
    USE SIGNAL ;
    SHAPE ABUTMENT ;
    PORT
      LAYER M3 ;
      RECT 36.495 0.000 36.513 0.054 ;
    END
  END r0_rd_out[20]
  PIN r0_rd_out[21]
    DIRECTION OUTPUT ;
    USE SIGNAL ;
    SHAPE ABUTMENT ;
    PORT
      LAYER M3 ;
      RECT 36.927 0.000 36.945 0.054 ;
    END
  END r0_rd_out[21]
  PIN r0_rd_out[22]
    DIRECTION OUTPUT ;
    USE SIGNAL ;
    SHAPE ABUTMENT ;
    PORT
      LAYER M3 ;
      RECT 37.359 0.000 37.377 0.054 ;
    END
  END r0_rd_out[22]
  PIN r0_rd_out[23]
    DIRECTION OUTPUT ;
    USE SIGNAL ;
    SHAPE ABUTMENT ;
    PORT
      LAYER M3 ;
      RECT 37.791 0.000 37.809 0.054 ;
    END
  END r0_rd_out[23]
  PIN r0_rd_out[24]
    DIRECTION OUTPUT ;
    USE SIGNAL ;
    SHAPE ABUTMENT ;
    PORT
      LAYER M3 ;
      RECT 38.223 0.000 38.241 0.054 ;
    END
  END r0_rd_out[24]
  PIN r0_rd_out[25]
    DIRECTION OUTPUT ;
    USE SIGNAL ;
    SHAPE ABUTMENT ;
    PORT
      LAYER M3 ;
      RECT 38.655 0.000 38.673 0.054 ;
    END
  END r0_rd_out[25]
  PIN r0_rd_out[26]
    DIRECTION OUTPUT ;
    USE SIGNAL ;
    SHAPE ABUTMENT ;
    PORT
      LAYER M3 ;
      RECT 39.087 0.000 39.105 0.054 ;
    END
  END r0_rd_out[26]
  PIN r0_rd_out[27]
    DIRECTION OUTPUT ;
    USE SIGNAL ;
    SHAPE ABUTMENT ;
    PORT
      LAYER M3 ;
      RECT 39.519 0.000 39.537 0.054 ;
    END
  END r0_rd_out[27]
  PIN r0_rd_out[28]
    DIRECTION OUTPUT ;
    USE SIGNAL ;
    SHAPE ABUTMENT ;
    PORT
      LAYER M3 ;
      RECT 39.951 0.000 39.969 0.054 ;
    END
  END r0_rd_out[28]
  PIN r0_rd_out[29]
    DIRECTION OUTPUT ;
    USE SIGNAL ;
    SHAPE ABUTMENT ;
    PORT
      LAYER M3 ;
      RECT 40.383 0.000 40.401 0.054 ;
    END
  END r0_rd_out[29]
  PIN r0_rd_out[30]
    DIRECTION OUTPUT ;
    USE SIGNAL ;
    SHAPE ABUTMENT ;
    PORT
      LAYER M3 ;
      RECT 40.815 0.000 40.833 0.054 ;
    END
  END r0_rd_out[30]
  PIN r0_rd_out[31]
    DIRECTION OUTPUT ;
    USE SIGNAL ;
    SHAPE ABUTMENT ;
    PORT
      LAYER M3 ;
      RECT 41.247 0.000 41.265 0.054 ;
    END
  END r0_rd_out[31]
  PIN r0_rd_out[32]
    DIRECTION OUTPUT ;
    USE SIGNAL ;
    SHAPE ABUTMENT ;
    PORT
      LAYER M3 ;
      RECT 41.679 0.000 41.697 0.054 ;
    END
  END r0_rd_out[32]
  PIN r0_rd_out[33]
    DIRECTION OUTPUT ;
    USE SIGNAL ;
    SHAPE ABUTMENT ;
    PORT
      LAYER M3 ;
      RECT 42.111 0.000 42.129 0.054 ;
    END
  END r0_rd_out[33]
  PIN r0_rd_out[34]
    DIRECTION OUTPUT ;
    USE SIGNAL ;
    SHAPE ABUTMENT ;
    PORT
      LAYER M3 ;
      RECT 42.543 0.000 42.561 0.054 ;
    END
  END r0_rd_out[34]
  PIN r0_rd_out[35]
    DIRECTION OUTPUT ;
    USE SIGNAL ;
    SHAPE ABUTMENT ;
    PORT
      LAYER M3 ;
      RECT 42.975 0.000 42.993 0.054 ;
    END
  END r0_rd_out[35]
  PIN r0_rd_out[36]
    DIRECTION OUTPUT ;
    USE SIGNAL ;
    SHAPE ABUTMENT ;
    PORT
      LAYER M3 ;
      RECT 43.407 0.000 43.425 0.054 ;
    END
  END r0_rd_out[36]
  PIN r0_rd_out[37]
    DIRECTION OUTPUT ;
    USE SIGNAL ;
    SHAPE ABUTMENT ;
    PORT
      LAYER M3 ;
      RECT 43.839 0.000 43.857 0.054 ;
    END
  END r0_rd_out[37]
  PIN r0_rd_out[38]
    DIRECTION OUTPUT ;
    USE SIGNAL ;
    SHAPE ABUTMENT ;
    PORT
      LAYER M3 ;
      RECT 44.271 0.000 44.289 0.054 ;
    END
  END r0_rd_out[38]
  PIN r0_rd_out[39]
    DIRECTION OUTPUT ;
    USE SIGNAL ;
    SHAPE ABUTMENT ;
    PORT
      LAYER M3 ;
      RECT 44.703 0.000 44.721 0.054 ;
    END
  END r0_rd_out[39]
  PIN r0_rd_out[40]
    DIRECTION OUTPUT ;
    USE SIGNAL ;
    SHAPE ABUTMENT ;
    PORT
      LAYER M3 ;
      RECT 45.135 0.000 45.153 0.054 ;
    END
  END r0_rd_out[40]
  PIN r0_rd_out[41]
    DIRECTION OUTPUT ;
    USE SIGNAL ;
    SHAPE ABUTMENT ;
    PORT
      LAYER M3 ;
      RECT 45.567 0.000 45.585 0.054 ;
    END
  END r0_rd_out[41]
  PIN r0_rd_out[42]
    DIRECTION OUTPUT ;
    USE SIGNAL ;
    SHAPE ABUTMENT ;
    PORT
      LAYER M3 ;
      RECT 45.999 0.000 46.017 0.054 ;
    END
  END r0_rd_out[42]
  PIN r0_rd_out[43]
    DIRECTION OUTPUT ;
    USE SIGNAL ;
    SHAPE ABUTMENT ;
    PORT
      LAYER M3 ;
      RECT 46.431 0.000 46.449 0.054 ;
    END
  END r0_rd_out[43]
  PIN r0_rd_out[44]
    DIRECTION OUTPUT ;
    USE SIGNAL ;
    SHAPE ABUTMENT ;
    PORT
      LAYER M3 ;
      RECT 46.863 0.000 46.881 0.054 ;
    END
  END r0_rd_out[44]
  PIN r0_rd_out[45]
    DIRECTION OUTPUT ;
    USE SIGNAL ;
    SHAPE ABUTMENT ;
    PORT
      LAYER M3 ;
      RECT 47.295 0.000 47.313 0.054 ;
    END
  END r0_rd_out[45]
  PIN r0_rd_out[46]
    DIRECTION OUTPUT ;
    USE SIGNAL ;
    SHAPE ABUTMENT ;
    PORT
      LAYER M3 ;
      RECT 47.727 0.000 47.745 0.054 ;
    END
  END r0_rd_out[46]
  PIN r0_rd_out[47]
    DIRECTION OUTPUT ;
    USE SIGNAL ;
    SHAPE ABUTMENT ;
    PORT
      LAYER M3 ;
      RECT 48.159 0.000 48.177 0.054 ;
    END
  END r0_rd_out[47]
  PIN r0_rd_out[48]
    DIRECTION OUTPUT ;
    USE SIGNAL ;
    SHAPE ABUTMENT ;
    PORT
      LAYER M3 ;
      RECT 48.591 0.000 48.609 0.054 ;
    END
  END r0_rd_out[48]
  PIN r0_rd_out[49]
    DIRECTION OUTPUT ;
    USE SIGNAL ;
    SHAPE ABUTMENT ;
    PORT
      LAYER M3 ;
      RECT 49.023 0.000 49.041 0.054 ;
    END
  END r0_rd_out[49]
  PIN r0_rd_out[50]
    DIRECTION OUTPUT ;
    USE SIGNAL ;
    SHAPE ABUTMENT ;
    PORT
      LAYER M3 ;
      RECT 49.455 0.000 49.473 0.054 ;
    END
  END r0_rd_out[50]
  PIN r0_rd_out[51]
    DIRECTION OUTPUT ;
    USE SIGNAL ;
    SHAPE ABUTMENT ;
    PORT
      LAYER M3 ;
      RECT 49.887 0.000 49.905 0.054 ;
    END
  END r0_rd_out[51]
  PIN r0_rd_out[52]
    DIRECTION OUTPUT ;
    USE SIGNAL ;
    SHAPE ABUTMENT ;
    PORT
      LAYER M3 ;
      RECT 50.319 0.000 50.337 0.054 ;
    END
  END r0_rd_out[52]
  PIN r0_rd_out[53]
    DIRECTION OUTPUT ;
    USE SIGNAL ;
    SHAPE ABUTMENT ;
    PORT
      LAYER M3 ;
      RECT 50.751 0.000 50.769 0.054 ;
    END
  END r0_rd_out[53]
  PIN r0_rd_out[54]
    DIRECTION OUTPUT ;
    USE SIGNAL ;
    SHAPE ABUTMENT ;
    PORT
      LAYER M3 ;
      RECT 51.183 0.000 51.201 0.054 ;
    END
  END r0_rd_out[54]
  PIN r0_rd_out[55]
    DIRECTION OUTPUT ;
    USE SIGNAL ;
    SHAPE ABUTMENT ;
    PORT
      LAYER M3 ;
      RECT 51.615 0.000 51.633 0.054 ;
    END
  END r0_rd_out[55]
  PIN r0_rd_out[56]
    DIRECTION OUTPUT ;
    USE SIGNAL ;
    SHAPE ABUTMENT ;
    PORT
      LAYER M3 ;
      RECT 52.047 0.000 52.065 0.054 ;
    END
  END r0_rd_out[56]
  PIN r0_rd_out[57]
    DIRECTION OUTPUT ;
    USE SIGNAL ;
    SHAPE ABUTMENT ;
    PORT
      LAYER M3 ;
      RECT 52.479 0.000 52.497 0.054 ;
    END
  END r0_rd_out[57]
  PIN r0_rd_out[58]
    DIRECTION OUTPUT ;
    USE SIGNAL ;
    SHAPE ABUTMENT ;
    PORT
      LAYER M3 ;
      RECT 52.911 0.000 52.929 0.054 ;
    END
  END r0_rd_out[58]
  PIN r0_rd_out[59]
    DIRECTION OUTPUT ;
    USE SIGNAL ;
    SHAPE ABUTMENT ;
    PORT
      LAYER M3 ;
      RECT 53.343 0.000 53.361 0.054 ;
    END
  END r0_rd_out[59]
  PIN r0_rd_out[60]
    DIRECTION OUTPUT ;
    USE SIGNAL ;
    SHAPE ABUTMENT ;
    PORT
      LAYER M3 ;
      RECT 53.775 0.000 53.793 0.054 ;
    END
  END r0_rd_out[60]
  PIN r0_rd_out[61]
    DIRECTION OUTPUT ;
    USE SIGNAL ;
    SHAPE ABUTMENT ;
    PORT
      LAYER M3 ;
      RECT 54.207 0.000 54.225 0.054 ;
    END
  END r0_rd_out[61]
  PIN r0_rd_out[62]
    DIRECTION OUTPUT ;
    USE SIGNAL ;
    SHAPE ABUTMENT ;
    PORT
      LAYER M3 ;
      RECT 54.639 0.000 54.657 0.054 ;
    END
  END r0_rd_out[62]
  PIN r0_rd_out[63]
    DIRECTION OUTPUT ;
    USE SIGNAL ;
    SHAPE ABUTMENT ;
    PORT
      LAYER M3 ;
      RECT 55.071 0.000 55.089 0.054 ;
    END
  END r0_rd_out[63]
  PIN r0_rd_out[64]
    DIRECTION OUTPUT ;
    USE SIGNAL ;
    SHAPE ABUTMENT ;
    PORT
      LAYER M3 ;
      RECT 25.551 70.794 25.569 70.848 ;
    END
  END r0_rd_out[64]
  PIN r0_rd_out[65]
    DIRECTION OUTPUT ;
    USE SIGNAL ;
    SHAPE ABUTMENT ;
    PORT
      LAYER M3 ;
      RECT 25.947 70.794 25.965 70.848 ;
    END
  END r0_rd_out[65]
  PIN r0_rd_out[66]
    DIRECTION OUTPUT ;
    USE SIGNAL ;
    SHAPE ABUTMENT ;
    PORT
      LAYER M3 ;
      RECT 26.343 70.794 26.361 70.848 ;
    END
  END r0_rd_out[66]
  PIN r0_rd_out[67]
    DIRECTION OUTPUT ;
    USE SIGNAL ;
    SHAPE ABUTMENT ;
    PORT
      LAYER M3 ;
      RECT 26.739 70.794 26.757 70.848 ;
    END
  END r0_rd_out[67]
  PIN r0_rd_out[68]
    DIRECTION OUTPUT ;
    USE SIGNAL ;
    SHAPE ABUTMENT ;
    PORT
      LAYER M3 ;
      RECT 27.135 70.794 27.153 70.848 ;
    END
  END r0_rd_out[68]
  PIN r0_rd_out[69]
    DIRECTION OUTPUT ;
    USE SIGNAL ;
    SHAPE ABUTMENT ;
    PORT
      LAYER M3 ;
      RECT 27.531 70.794 27.549 70.848 ;
    END
  END r0_rd_out[69]
  PIN r0_rd_out[70]
    DIRECTION OUTPUT ;
    USE SIGNAL ;
    SHAPE ABUTMENT ;
    PORT
      LAYER M3 ;
      RECT 27.927 70.794 27.945 70.848 ;
    END
  END r0_rd_out[70]
  PIN r0_rd_out[71]
    DIRECTION OUTPUT ;
    USE SIGNAL ;
    SHAPE ABUTMENT ;
    PORT
      LAYER M3 ;
      RECT 28.323 70.794 28.341 70.848 ;
    END
  END r0_rd_out[71]
  PIN r0_rd_out[72]
    DIRECTION OUTPUT ;
    USE SIGNAL ;
    SHAPE ABUTMENT ;
    PORT
      LAYER M3 ;
      RECT 28.719 70.794 28.737 70.848 ;
    END
  END r0_rd_out[72]
  PIN r0_rd_out[73]
    DIRECTION OUTPUT ;
    USE SIGNAL ;
    SHAPE ABUTMENT ;
    PORT
      LAYER M3 ;
      RECT 29.115 70.794 29.133 70.848 ;
    END
  END r0_rd_out[73]
  PIN r0_rd_out[74]
    DIRECTION OUTPUT ;
    USE SIGNAL ;
    SHAPE ABUTMENT ;
    PORT
      LAYER M3 ;
      RECT 29.511 70.794 29.529 70.848 ;
    END
  END r0_rd_out[74]
  PIN r0_rd_out[75]
    DIRECTION OUTPUT ;
    USE SIGNAL ;
    SHAPE ABUTMENT ;
    PORT
      LAYER M3 ;
      RECT 29.907 70.794 29.925 70.848 ;
    END
  END r0_rd_out[75]
  PIN r0_rd_out[76]
    DIRECTION OUTPUT ;
    USE SIGNAL ;
    SHAPE ABUTMENT ;
    PORT
      LAYER M3 ;
      RECT 30.303 70.794 30.321 70.848 ;
    END
  END r0_rd_out[76]
  PIN r0_rd_out[77]
    DIRECTION OUTPUT ;
    USE SIGNAL ;
    SHAPE ABUTMENT ;
    PORT
      LAYER M3 ;
      RECT 30.699 70.794 30.717 70.848 ;
    END
  END r0_rd_out[77]
  PIN r0_rd_out[78]
    DIRECTION OUTPUT ;
    USE SIGNAL ;
    SHAPE ABUTMENT ;
    PORT
      LAYER M3 ;
      RECT 31.095 70.794 31.113 70.848 ;
    END
  END r0_rd_out[78]
  PIN r0_rd_out[79]
    DIRECTION OUTPUT ;
    USE SIGNAL ;
    SHAPE ABUTMENT ;
    PORT
      LAYER M3 ;
      RECT 31.491 70.794 31.509 70.848 ;
    END
  END r0_rd_out[79]
  PIN r0_rd_out[80]
    DIRECTION OUTPUT ;
    USE SIGNAL ;
    SHAPE ABUTMENT ;
    PORT
      LAYER M3 ;
      RECT 31.887 70.794 31.905 70.848 ;
    END
  END r0_rd_out[80]
  PIN r0_rd_out[81]
    DIRECTION OUTPUT ;
    USE SIGNAL ;
    SHAPE ABUTMENT ;
    PORT
      LAYER M3 ;
      RECT 32.283 70.794 32.301 70.848 ;
    END
  END r0_rd_out[81]
  PIN r0_rd_out[82]
    DIRECTION OUTPUT ;
    USE SIGNAL ;
    SHAPE ABUTMENT ;
    PORT
      LAYER M3 ;
      RECT 32.679 70.794 32.697 70.848 ;
    END
  END r0_rd_out[82]
  PIN r0_rd_out[83]
    DIRECTION OUTPUT ;
    USE SIGNAL ;
    SHAPE ABUTMENT ;
    PORT
      LAYER M3 ;
      RECT 33.075 70.794 33.093 70.848 ;
    END
  END r0_rd_out[83]
  PIN r0_rd_out[84]
    DIRECTION OUTPUT ;
    USE SIGNAL ;
    SHAPE ABUTMENT ;
    PORT
      LAYER M3 ;
      RECT 33.471 70.794 33.489 70.848 ;
    END
  END r0_rd_out[84]
  PIN r0_rd_out[85]
    DIRECTION OUTPUT ;
    USE SIGNAL ;
    SHAPE ABUTMENT ;
    PORT
      LAYER M3 ;
      RECT 33.867 70.794 33.885 70.848 ;
    END
  END r0_rd_out[85]
  PIN r0_rd_out[86]
    DIRECTION OUTPUT ;
    USE SIGNAL ;
    SHAPE ABUTMENT ;
    PORT
      LAYER M3 ;
      RECT 34.263 70.794 34.281 70.848 ;
    END
  END r0_rd_out[86]
  PIN r0_rd_out[87]
    DIRECTION OUTPUT ;
    USE SIGNAL ;
    SHAPE ABUTMENT ;
    PORT
      LAYER M3 ;
      RECT 34.659 70.794 34.677 70.848 ;
    END
  END r0_rd_out[87]
  PIN r0_rd_out[88]
    DIRECTION OUTPUT ;
    USE SIGNAL ;
    SHAPE ABUTMENT ;
    PORT
      LAYER M3 ;
      RECT 35.055 70.794 35.073 70.848 ;
    END
  END r0_rd_out[88]
  PIN r0_rd_out[89]
    DIRECTION OUTPUT ;
    USE SIGNAL ;
    SHAPE ABUTMENT ;
    PORT
      LAYER M3 ;
      RECT 35.451 70.794 35.469 70.848 ;
    END
  END r0_rd_out[89]
  PIN r0_rd_out[90]
    DIRECTION OUTPUT ;
    USE SIGNAL ;
    SHAPE ABUTMENT ;
    PORT
      LAYER M3 ;
      RECT 35.847 70.794 35.865 70.848 ;
    END
  END r0_rd_out[90]
  PIN r0_rd_out[91]
    DIRECTION OUTPUT ;
    USE SIGNAL ;
    SHAPE ABUTMENT ;
    PORT
      LAYER M3 ;
      RECT 36.243 70.794 36.261 70.848 ;
    END
  END r0_rd_out[91]
  PIN r0_rd_out[92]
    DIRECTION OUTPUT ;
    USE SIGNAL ;
    SHAPE ABUTMENT ;
    PORT
      LAYER M3 ;
      RECT 36.639 70.794 36.657 70.848 ;
    END
  END r0_rd_out[92]
  PIN r0_rd_out[93]
    DIRECTION OUTPUT ;
    USE SIGNAL ;
    SHAPE ABUTMENT ;
    PORT
      LAYER M3 ;
      RECT 37.035 70.794 37.053 70.848 ;
    END
  END r0_rd_out[93]
  PIN r0_rd_out[94]
    DIRECTION OUTPUT ;
    USE SIGNAL ;
    SHAPE ABUTMENT ;
    PORT
      LAYER M3 ;
      RECT 37.431 70.794 37.449 70.848 ;
    END
  END r0_rd_out[94]
  PIN r0_rd_out[95]
    DIRECTION OUTPUT ;
    USE SIGNAL ;
    SHAPE ABUTMENT ;
    PORT
      LAYER M3 ;
      RECT 37.827 70.794 37.845 70.848 ;
    END
  END r0_rd_out[95]
  PIN r0_rd_out[96]
    DIRECTION OUTPUT ;
    USE SIGNAL ;
    SHAPE ABUTMENT ;
    PORT
      LAYER M3 ;
      RECT 38.223 70.794 38.241 70.848 ;
    END
  END r0_rd_out[96]
  PIN r0_rd_out[97]
    DIRECTION OUTPUT ;
    USE SIGNAL ;
    SHAPE ABUTMENT ;
    PORT
      LAYER M3 ;
      RECT 38.619 70.794 38.637 70.848 ;
    END
  END r0_rd_out[97]
  PIN r0_rd_out[98]
    DIRECTION OUTPUT ;
    USE SIGNAL ;
    SHAPE ABUTMENT ;
    PORT
      LAYER M3 ;
      RECT 39.015 70.794 39.033 70.848 ;
    END
  END r0_rd_out[98]
  PIN r0_rd_out[99]
    DIRECTION OUTPUT ;
    USE SIGNAL ;
    SHAPE ABUTMENT ;
    PORT
      LAYER M3 ;
      RECT 39.411 70.794 39.429 70.848 ;
    END
  END r0_rd_out[99]
  PIN r0_rd_out[100]
    DIRECTION OUTPUT ;
    USE SIGNAL ;
    SHAPE ABUTMENT ;
    PORT
      LAYER M3 ;
      RECT 39.807 70.794 39.825 70.848 ;
    END
  END r0_rd_out[100]
  PIN r0_rd_out[101]
    DIRECTION OUTPUT ;
    USE SIGNAL ;
    SHAPE ABUTMENT ;
    PORT
      LAYER M3 ;
      RECT 40.203 70.794 40.221 70.848 ;
    END
  END r0_rd_out[101]
  PIN r0_rd_out[102]
    DIRECTION OUTPUT ;
    USE SIGNAL ;
    SHAPE ABUTMENT ;
    PORT
      LAYER M3 ;
      RECT 40.599 70.794 40.617 70.848 ;
    END
  END r0_rd_out[102]
  PIN r0_rd_out[103]
    DIRECTION OUTPUT ;
    USE SIGNAL ;
    SHAPE ABUTMENT ;
    PORT
      LAYER M3 ;
      RECT 40.995 70.794 41.013 70.848 ;
    END
  END r0_rd_out[103]
  PIN r0_rd_out[104]
    DIRECTION OUTPUT ;
    USE SIGNAL ;
    SHAPE ABUTMENT ;
    PORT
      LAYER M3 ;
      RECT 41.391 70.794 41.409 70.848 ;
    END
  END r0_rd_out[104]
  PIN r0_rd_out[105]
    DIRECTION OUTPUT ;
    USE SIGNAL ;
    SHAPE ABUTMENT ;
    PORT
      LAYER M3 ;
      RECT 41.787 70.794 41.805 70.848 ;
    END
  END r0_rd_out[105]
  PIN r0_rd_out[106]
    DIRECTION OUTPUT ;
    USE SIGNAL ;
    SHAPE ABUTMENT ;
    PORT
      LAYER M3 ;
      RECT 42.183 70.794 42.201 70.848 ;
    END
  END r0_rd_out[106]
  PIN r0_rd_out[107]
    DIRECTION OUTPUT ;
    USE SIGNAL ;
    SHAPE ABUTMENT ;
    PORT
      LAYER M3 ;
      RECT 42.579 70.794 42.597 70.848 ;
    END
  END r0_rd_out[107]
  PIN r0_rd_out[108]
    DIRECTION OUTPUT ;
    USE SIGNAL ;
    SHAPE ABUTMENT ;
    PORT
      LAYER M3 ;
      RECT 42.975 70.794 42.993 70.848 ;
    END
  END r0_rd_out[108]
  PIN r0_rd_out[109]
    DIRECTION OUTPUT ;
    USE SIGNAL ;
    SHAPE ABUTMENT ;
    PORT
      LAYER M3 ;
      RECT 43.371 70.794 43.389 70.848 ;
    END
  END r0_rd_out[109]
  PIN r0_rd_out[110]
    DIRECTION OUTPUT ;
    USE SIGNAL ;
    SHAPE ABUTMENT ;
    PORT
      LAYER M3 ;
      RECT 43.767 70.794 43.785 70.848 ;
    END
  END r0_rd_out[110]
  PIN r0_rd_out[111]
    DIRECTION OUTPUT ;
    USE SIGNAL ;
    SHAPE ABUTMENT ;
    PORT
      LAYER M3 ;
      RECT 44.163 70.794 44.181 70.848 ;
    END
  END r0_rd_out[111]
  PIN r0_rd_out[112]
    DIRECTION OUTPUT ;
    USE SIGNAL ;
    SHAPE ABUTMENT ;
    PORT
      LAYER M3 ;
      RECT 44.559 70.794 44.577 70.848 ;
    END
  END r0_rd_out[112]
  PIN r0_rd_out[113]
    DIRECTION OUTPUT ;
    USE SIGNAL ;
    SHAPE ABUTMENT ;
    PORT
      LAYER M3 ;
      RECT 44.955 70.794 44.973 70.848 ;
    END
  END r0_rd_out[113]
  PIN r0_rd_out[114]
    DIRECTION OUTPUT ;
    USE SIGNAL ;
    SHAPE ABUTMENT ;
    PORT
      LAYER M3 ;
      RECT 45.351 70.794 45.369 70.848 ;
    END
  END r0_rd_out[114]
  PIN r0_rd_out[115]
    DIRECTION OUTPUT ;
    USE SIGNAL ;
    SHAPE ABUTMENT ;
    PORT
      LAYER M3 ;
      RECT 45.747 70.794 45.765 70.848 ;
    END
  END r0_rd_out[115]
  PIN r0_rd_out[116]
    DIRECTION OUTPUT ;
    USE SIGNAL ;
    SHAPE ABUTMENT ;
    PORT
      LAYER M3 ;
      RECT 46.143 70.794 46.161 70.848 ;
    END
  END r0_rd_out[116]
  PIN r0_rd_out[117]
    DIRECTION OUTPUT ;
    USE SIGNAL ;
    SHAPE ABUTMENT ;
    PORT
      LAYER M3 ;
      RECT 46.539 70.794 46.557 70.848 ;
    END
  END r0_rd_out[117]
  PIN r0_rd_out[118]
    DIRECTION OUTPUT ;
    USE SIGNAL ;
    SHAPE ABUTMENT ;
    PORT
      LAYER M3 ;
      RECT 46.935 70.794 46.953 70.848 ;
    END
  END r0_rd_out[118]
  PIN r0_rd_out[119]
    DIRECTION OUTPUT ;
    USE SIGNAL ;
    SHAPE ABUTMENT ;
    PORT
      LAYER M3 ;
      RECT 47.331 70.794 47.349 70.848 ;
    END
  END r0_rd_out[119]
  PIN r0_rd_out[120]
    DIRECTION OUTPUT ;
    USE SIGNAL ;
    SHAPE ABUTMENT ;
    PORT
      LAYER M3 ;
      RECT 47.727 70.794 47.745 70.848 ;
    END
  END r0_rd_out[120]
  PIN r0_rd_out[121]
    DIRECTION OUTPUT ;
    USE SIGNAL ;
    SHAPE ABUTMENT ;
    PORT
      LAYER M3 ;
      RECT 48.123 70.794 48.141 70.848 ;
    END
  END r0_rd_out[121]
  PIN r0_rd_out[122]
    DIRECTION OUTPUT ;
    USE SIGNAL ;
    SHAPE ABUTMENT ;
    PORT
      LAYER M3 ;
      RECT 48.519 70.794 48.537 70.848 ;
    END
  END r0_rd_out[122]
  PIN r0_rd_out[123]
    DIRECTION OUTPUT ;
    USE SIGNAL ;
    SHAPE ABUTMENT ;
    PORT
      LAYER M3 ;
      RECT 48.915 70.794 48.933 70.848 ;
    END
  END r0_rd_out[123]
  PIN r0_rd_out[124]
    DIRECTION OUTPUT ;
    USE SIGNAL ;
    SHAPE ABUTMENT ;
    PORT
      LAYER M3 ;
      RECT 49.311 70.794 49.329 70.848 ;
    END
  END r0_rd_out[124]
  PIN r0_rd_out[125]
    DIRECTION OUTPUT ;
    USE SIGNAL ;
    SHAPE ABUTMENT ;
    PORT
      LAYER M3 ;
      RECT 49.707 70.794 49.725 70.848 ;
    END
  END r0_rd_out[125]
  PIN r0_rd_out[126]
    DIRECTION OUTPUT ;
    USE SIGNAL ;
    SHAPE ABUTMENT ;
    PORT
      LAYER M3 ;
      RECT 50.103 70.794 50.121 70.848 ;
    END
  END r0_rd_out[126]
  PIN r0_rd_out[127]
    DIRECTION OUTPUT ;
    USE SIGNAL ;
    SHAPE ABUTMENT ;
    PORT
      LAYER M3 ;
      RECT 50.499 70.794 50.517 70.848 ;
    END
  END r0_rd_out[127]
  PIN w0_addr_in[0]
    DIRECTION INPUT ;
    USE SIGNAL ;
    SHAPE ABUTMENT ;
    PORT
      LAYER M4 ;
      RECT 0.000 61.716 0.072 61.740 ;
    END
  END w0_addr_in[0]
  PIN w0_addr_in[1]
    DIRECTION INPUT ;
    USE SIGNAL ;
    SHAPE ABUTMENT ;
    PORT
      LAYER M4 ;
      RECT 0.000 62.676 0.072 62.700 ;
    END
  END w0_addr_in[1]
  PIN w0_addr_in[2]
    DIRECTION INPUT ;
    USE SIGNAL ;
    SHAPE ABUTMENT ;
    PORT
      LAYER M4 ;
      RECT 0.000 63.636 0.072 63.660 ;
    END
  END w0_addr_in[2]
  PIN w0_addr_in[3]
    DIRECTION INPUT ;
    USE SIGNAL ;
    SHAPE ABUTMENT ;
    PORT
      LAYER M4 ;
      RECT 56.607 61.716 56.679 61.740 ;
    END
  END w0_addr_in[3]
  PIN w0_addr_in[4]
    DIRECTION INPUT ;
    USE SIGNAL ;
    SHAPE ABUTMENT ;
    PORT
      LAYER M4 ;
      RECT 56.607 62.676 56.679 62.700 ;
    END
  END w0_addr_in[4]
  PIN w0_addr_in[5]
    DIRECTION INPUT ;
    USE SIGNAL ;
    SHAPE ABUTMENT ;
    PORT
      LAYER M4 ;
      RECT 56.607 63.636 56.679 63.660 ;
    END
  END w0_addr_in[5]
  PIN r0_addr_in[0]
    DIRECTION INPUT ;
    USE SIGNAL ;
    SHAPE ABUTMENT ;
    PORT
      LAYER M4 ;
      RECT 0.000 64.596 0.072 64.620 ;
    END
  END r0_addr_in[0]
  PIN r0_addr_in[1]
    DIRECTION INPUT ;
    USE SIGNAL ;
    SHAPE ABUTMENT ;
    PORT
      LAYER M4 ;
      RECT 0.000 65.556 0.072 65.580 ;
    END
  END r0_addr_in[1]
  PIN r0_addr_in[2]
    DIRECTION INPUT ;
    USE SIGNAL ;
    SHAPE ABUTMENT ;
    PORT
      LAYER M4 ;
      RECT 0.000 66.516 0.072 66.540 ;
    END
  END r0_addr_in[2]
  PIN r0_addr_in[3]
    DIRECTION INPUT ;
    USE SIGNAL ;
    SHAPE ABUTMENT ;
    PORT
      LAYER M4 ;
      RECT 56.607 64.596 56.679 64.620 ;
    END
  END r0_addr_in[3]
  PIN r0_addr_in[4]
    DIRECTION INPUT ;
    USE SIGNAL ;
    SHAPE ABUTMENT ;
    PORT
      LAYER M4 ;
      RECT 56.607 65.556 56.679 65.580 ;
    END
  END r0_addr_in[4]
  PIN r0_addr_in[5]
    DIRECTION INPUT ;
    USE SIGNAL ;
    SHAPE ABUTMENT ;
    PORT
      LAYER M4 ;
      RECT 56.607 66.516 56.679 66.540 ;
    END
  END r0_addr_in[5]
  PIN w0_we_in
    DIRECTION INPUT ;
    USE SIGNAL ;
    SHAPE ABUTMENT ;
    PORT
      LAYER M3 ;
      RECT 50.895 70.794 50.913 70.848 ;
    END
  END w0_we_in
  PIN w0_ce_in
    DIRECTION INPUT ;
    USE SIGNAL ;
    SHAPE ABUTMENT ;
    PORT
      LAYER M3 ;
      RECT 51.291 70.794 51.309 70.848 ;
    END
  END w0_ce_in
  PIN w0_clk
    DIRECTION INPUT ;
    USE SIGNAL ;
    SHAPE ABUTMENT ;
    PORT
      LAYER M3 ;
      RECT 51.687 70.794 51.705 70.848 ;
    END
  END w0_clk
  PIN r0_ce_in
    DIRECTION INPUT ;
    USE SIGNAL ;
    SHAPE ABUTMENT ;
    PORT
      LAYER M3 ;
      RECT 52.083 70.794 52.101 70.848 ;
    END
  END r0_ce_in
  PIN r0_clk
    DIRECTION INPUT ;
    USE SIGNAL ;
    SHAPE ABUTMENT ;
    PORT
      LAYER M3 ;
      RECT 52.479 70.794 52.497 70.848 ;
    END
  END r0_clk
  PIN VSS
    DIRECTION INOUT ;
    USE GROUND ;
    PORT
      LAYER M4 ;
      RECT 0.216 0.240 56.463 0.336 ;
      RECT 0.216 1.008 56.463 1.104 ;
      RECT 0.216 1.776 56.463 1.872 ;
      RECT 0.216 2.544 56.463 2.640 ;
      RECT 0.216 3.312 56.463 3.408 ;
      RECT 0.216 4.080 56.463 4.176 ;
      RECT 0.216 4.848 56.463 4.944 ;
      RECT 0.216 5.616 56.463 5.712 ;
      RECT 0.216 6.384 56.463 6.480 ;
      RECT 0.216 7.152 56.463 7.248 ;
      RECT 0.216 7.920 56.463 8.016 ;
      RECT 0.216 8.688 56.463 8.784 ;
      RECT 0.216 9.456 56.463 9.552 ;
      RECT 0.216 10.224 56.463 10.320 ;
      RECT 0.216 10.992 56.463 11.088 ;
      RECT 0.216 11.760 56.463 11.856 ;
      RECT 0.216 12.528 56.463 12.624 ;
      RECT 0.216 13.296 56.463 13.392 ;
      RECT 0.216 14.064 56.463 14.160 ;
      RECT 0.216 14.832 56.463 14.928 ;
      RECT 0.216 15.600 56.463 15.696 ;
      RECT 0.216 16.368 56.463 16.464 ;
      RECT 0.216 17.136 56.463 17.232 ;
      RECT 0.216 17.904 56.463 18.000 ;
      RECT 0.216 18.672 56.463 18.768 ;
      RECT 0.216 19.440 56.463 19.536 ;
      RECT 0.216 20.208 56.463 20.304 ;
      RECT 0.216 20.976 56.463 21.072 ;
      RECT 0.216 21.744 56.463 21.840 ;
      RECT 0.216 22.512 56.463 22.608 ;
      RECT 0.216 23.280 56.463 23.376 ;
      RECT 0.216 24.048 56.463 24.144 ;
      RECT 0.216 24.816 56.463 24.912 ;
      RECT 0.216 25.584 56.463 25.680 ;
      RECT 0.216 26.352 56.463 26.448 ;
      RECT 0.216 27.120 56.463 27.216 ;
      RECT 0.216 27.888 56.463 27.984 ;
      RECT 0.216 28.656 56.463 28.752 ;
      RECT 0.216 29.424 56.463 29.520 ;
      RECT 0.216 30.192 56.463 30.288 ;
      RECT 0.216 30.960 56.463 31.056 ;
      RECT 0.216 31.728 56.463 31.824 ;
      RECT 0.216 32.496 56.463 32.592 ;
      RECT 0.216 33.264 56.463 33.360 ;
      RECT 0.216 34.032 56.463 34.128 ;
      RECT 0.216 34.800 56.463 34.896 ;
      RECT 0.216 35.568 56.463 35.664 ;
      RECT 0.216 36.336 56.463 36.432 ;
      RECT 0.216 37.104 56.463 37.200 ;
      RECT 0.216 37.872 56.463 37.968 ;
      RECT 0.216 38.640 56.463 38.736 ;
      RECT 0.216 39.408 56.463 39.504 ;
      RECT 0.216 40.176 56.463 40.272 ;
      RECT 0.216 40.944 56.463 41.040 ;
      RECT 0.216 41.712 56.463 41.808 ;
      RECT 0.216 42.480 56.463 42.576 ;
      RECT 0.216 43.248 56.463 43.344 ;
      RECT 0.216 44.016 56.463 44.112 ;
      RECT 0.216 44.784 56.463 44.880 ;
      RECT 0.216 45.552 56.463 45.648 ;
      RECT 0.216 46.320 56.463 46.416 ;
      RECT 0.216 47.088 56.463 47.184 ;
      RECT 0.216 47.856 56.463 47.952 ;
      RECT 0.216 48.624 56.463 48.720 ;
      RECT 0.216 49.392 56.463 49.488 ;
      RECT 0.216 50.160 56.463 50.256 ;
      RECT 0.216 50.928 56.463 51.024 ;
      RECT 0.216 51.696 56.463 51.792 ;
      RECT 0.216 52.464 56.463 52.560 ;
      RECT 0.216 53.232 56.463 53.328 ;
      RECT 0.216 54.000 56.463 54.096 ;
      RECT 0.216 54.768 56.463 54.864 ;
      RECT 0.216 55.536 56.463 55.632 ;
      RECT 0.216 56.304 56.463 56.400 ;
      RECT 0.216 57.072 56.463 57.168 ;
      RECT 0.216 57.840 56.463 57.936 ;
      RECT 0.216 58.608 56.463 58.704 ;
      RECT 0.216 59.376 56.463 59.472 ;
      RECT 0.216 60.144 56.463 60.240 ;
      RECT 0.216 60.912 56.463 61.008 ;
      RECT 0.216 61.680 56.463 61.776 ;
      RECT 0.216 62.448 56.463 62.544 ;
      RECT 0.216 63.216 56.463 63.312 ;
      RECT 0.216 63.984 56.463 64.080 ;
      RECT 0.216 64.752 56.463 64.848 ;
      RECT 0.216 65.520 56.463 65.616 ;
      RECT 0.216 66.288 56.463 66.384 ;
      RECT 0.216 67.056 56.463 67.152 ;
      RECT 0.216 67.824 56.463 67.920 ;
      RECT 0.216 68.592 56.463 68.688 ;
      RECT 0.216 69.360 56.463 69.456 ;
      RECT 0.216 70.128 56.463 70.224 ;
    END
  END VSS
  PIN VDD
    DIRECTION INOUT ;
    USE POWER ;
    PORT
      LAYER M4 ;
      RECT 0.216 0.624 56.463 0.720 ;
      RECT 0.216 1.392 56.463 1.488 ;
      RECT 0.216 2.160 56.463 2.256 ;
      RECT 0.216 2.928 56.463 3.024 ;
      RECT 0.216 3.696 56.463 3.792 ;
      RECT 0.216 4.464 56.463 4.560 ;
      RECT 0.216 5.232 56.463 5.328 ;
      RECT 0.216 6.000 56.463 6.096 ;
      RECT 0.216 6.768 56.463 6.864 ;
      RECT 0.216 7.536 56.463 7.632 ;
      RECT 0.216 8.304 56.463 8.400 ;
      RECT 0.216 9.072 56.463 9.168 ;
      RECT 0.216 9.840 56.463 9.936 ;
      RECT 0.216 10.608 56.463 10.704 ;
      RECT 0.216 11.376 56.463 11.472 ;
      RECT 0.216 12.144 56.463 12.240 ;
      RECT 0.216 12.912 56.463 13.008 ;
      RECT 0.216 13.680 56.463 13.776 ;
      RECT 0.216 14.448 56.463 14.544 ;
      RECT 0.216 15.216 56.463 15.312 ;
      RECT 0.216 15.984 56.463 16.080 ;
      RECT 0.216 16.752 56.463 16.848 ;
      RECT 0.216 17.520 56.463 17.616 ;
      RECT 0.216 18.288 56.463 18.384 ;
      RECT 0.216 19.056 56.463 19.152 ;
      RECT 0.216 19.824 56.463 19.920 ;
      RECT 0.216 20.592 56.463 20.688 ;
      RECT 0.216 21.360 56.463 21.456 ;
      RECT 0.216 22.128 56.463 22.224 ;
      RECT 0.216 22.896 56.463 22.992 ;
      RECT 0.216 23.664 56.463 23.760 ;
      RECT 0.216 24.432 56.463 24.528 ;
      RECT 0.216 25.200 56.463 25.296 ;
      RECT 0.216 25.968 56.463 26.064 ;
      RECT 0.216 26.736 56.463 26.832 ;
      RECT 0.216 27.504 56.463 27.600 ;
      RECT 0.216 28.272 56.463 28.368 ;
      RECT 0.216 29.040 56.463 29.136 ;
      RECT 0.216 29.808 56.463 29.904 ;
      RECT 0.216 30.576 56.463 30.672 ;
      RECT 0.216 31.344 56.463 31.440 ;
      RECT 0.216 32.112 56.463 32.208 ;
      RECT 0.216 32.880 56.463 32.976 ;
      RECT 0.216 33.648 56.463 33.744 ;
      RECT 0.216 34.416 56.463 34.512 ;
      RECT 0.216 35.184 56.463 35.280 ;
      RECT 0.216 35.952 56.463 36.048 ;
      RECT 0.216 36.720 56.463 36.816 ;
      RECT 0.216 37.488 56.463 37.584 ;
      RECT 0.216 38.256 56.463 38.352 ;
      RECT 0.216 39.024 56.463 39.120 ;
      RECT 0.216 39.792 56.463 39.888 ;
      RECT 0.216 40.560 56.463 40.656 ;
      RECT 0.216 41.328 56.463 41.424 ;
      RECT 0.216 42.096 56.463 42.192 ;
      RECT 0.216 42.864 56.463 42.960 ;
      RECT 0.216 43.632 56.463 43.728 ;
      RECT 0.216 44.400 56.463 44.496 ;
      RECT 0.216 45.168 56.463 45.264 ;
      RECT 0.216 45.936 56.463 46.032 ;
      RECT 0.216 46.704 56.463 46.800 ;
      RECT 0.216 47.472 56.463 47.568 ;
      RECT 0.216 48.240 56.463 48.336 ;
      RECT 0.216 49.008 56.463 49.104 ;
      RECT 0.216 49.776 56.463 49.872 ;
      RECT 0.216 50.544 56.463 50.640 ;
      RECT 0.216 51.312 56.463 51.408 ;
      RECT 0.216 52.080 56.463 52.176 ;
      RECT 0.216 52.848 56.463 52.944 ;
      RECT 0.216 53.616 56.463 53.712 ;
      RECT 0.216 54.384 56.463 54.480 ;
      RECT 0.216 55.152 56.463 55.248 ;
      RECT 0.216 55.920 56.463 56.016 ;
      RECT 0.216 56.688 56.463 56.784 ;
      RECT 0.216 57.456 56.463 57.552 ;
      RECT 0.216 58.224 56.463 58.320 ;
      RECT 0.216 58.992 56.463 59.088 ;
      RECT 0.216 59.760 56.463 59.856 ;
      RECT 0.216 60.528 56.463 60.624 ;
      RECT 0.216 61.296 56.463 61.392 ;
      RECT 0.216 62.064 56.463 62.160 ;
      RECT 0.216 62.832 56.463 62.928 ;
      RECT 0.216 63.600 56.463 63.696 ;
      RECT 0.216 64.368 56.463 64.464 ;
      RECT 0.216 65.136 56.463 65.232 ;
      RECT 0.216 65.904 56.463 66.000 ;
      RECT 0.216 66.672 56.463 66.768 ;
      RECT 0.216 67.440 56.463 67.536 ;
      RECT 0.216 68.208 56.463 68.304 ;
      RECT 0.216 68.976 56.463 69.072 ;
      RECT 0.216 69.744 56.463 69.840 ;
      RECT 0.216 70.512 56.463 70.608 ;
    END
  END VDD
  OBS
    LAYER M1 ;
    RECT 0 0 56.679 70.848 ;
    LAYER M2 ;
    RECT 0 0 56.679 70.848 ;
    LAYER M3 ;
    RECT 0 0 56.679 70.848 ;
    LAYER M4 ;
    RECT 0 0 56.679 70.848 ;
  END
END fakeram_128x64_1r1w

END LIBRARY
